VERSION 5.8 ;
BUSBITCHARS "[]" ;
DIVIDERCHAR "/" ;
UNITS
    DATABASE MICRONS 1000 ;
END UNITS

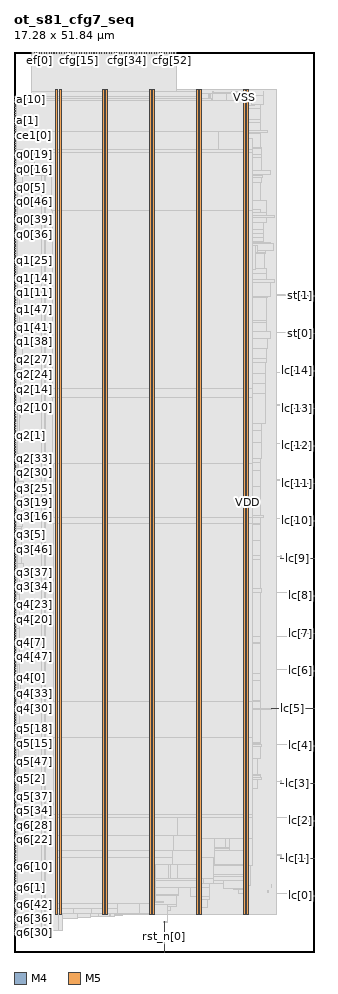
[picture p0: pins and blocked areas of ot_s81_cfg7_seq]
MACRO ot_s81_cfg7_seq
  FOREIGN ot_s81_cfg7_seq 0 0 ;
  CLASS BLOCK ;
  SIZE 17.28 BY 51.84 ;
  PIN a[0]
    DIRECTION OUTPUT ;
    USE SIGNAL ;
    PORT
      LAYER M4 ;
        RECT  0 47.76 0.084 47.784 ;
    END
  END a[0]
  PIN a[10]
    DIRECTION OUTPUT ;
    USE SIGNAL ;
    PORT
      LAYER M4 ;
        RECT  0 49.104 0.084 49.128 ;
    END
  END a[10]
  PIN a[11]
    DIRECTION OUTPUT ;
    USE SIGNAL ;
    PORT
      LAYER M4 ;
        RECT  0 49.248 0.084 49.272 ;
    END
  END a[11]
  PIN a[1]
    DIRECTION OUTPUT ;
    USE SIGNAL ;
    PORT
      LAYER M4 ;
        RECT  0 47.904 0.084 47.928 ;
    END
  END a[1]
  PIN a[2]
    DIRECTION OUTPUT ;
    USE SIGNAL ;
    PORT
      LAYER M4 ;
        RECT  0 48.048 0.084 48.072 ;
    END
  END a[2]
  PIN a[3]
    DIRECTION OUTPUT ;
    USE SIGNAL ;
    PORT
      LAYER M4 ;
        RECT  0 48.144 0.084 48.168 ;
    END
  END a[3]
  PIN a[4]
    DIRECTION OUTPUT ;
    USE SIGNAL ;
    PORT
      LAYER M4 ;
        RECT  0 48.288 0.084 48.312 ;
    END
  END a[4]
  PIN a[5]
    DIRECTION OUTPUT ;
    USE SIGNAL ;
    PORT
      LAYER M4 ;
        RECT  0 48.432 0.084 48.456 ;
    END
  END a[5]
  PIN a[6]
    DIRECTION OUTPUT ;
    USE SIGNAL ;
    PORT
      LAYER M4 ;
        RECT  0 48.576 0.084 48.6 ;
    END
  END a[6]
  PIN a[7]
    DIRECTION OUTPUT ;
    USE SIGNAL ;
    PORT
      LAYER M4 ;
        RECT  0 48.72 0.084 48.744 ;
    END
  END a[7]
  PIN a[8]
    DIRECTION OUTPUT ;
    USE SIGNAL ;
    PORT
      LAYER M4 ;
        RECT  0 48.816 0.084 48.84 ;
    END
  END a[8]
  PIN a[9]
    DIRECTION OUTPUT ;
    USE SIGNAL ;
    PORT
      LAYER M4 ;
        RECT  0 48.96 0.084 48.984 ;
    END
  END a[9]
  PIN ce0[0]
    DIRECTION OUTPUT ;
    USE SIGNAL ;
    PORT
      LAYER M4 ;
        RECT  0 47.616 0.084 47.64 ;
    END
  END ce0[0]
  PIN ce1[0]
    DIRECTION OUTPUT ;
    USE SIGNAL ;
    PORT
      LAYER M4 ;
        RECT  0 47.472 0.084 47.496 ;
    END
  END ce1[0]
  PIN ce2[0]
    DIRECTION OUTPUT ;
    USE SIGNAL ;
    PORT
      LAYER M4 ;
        RECT  0 47.376 0.084 47.4 ;
    END
  END ce2[0]
  PIN ce3[0]
    DIRECTION OUTPUT ;
    USE SIGNAL ;
    PORT
      LAYER M4 ;
        RECT  0 47.232 0.084 47.256 ;
    END
  END ce3[0]
  PIN ce4[0]
    DIRECTION OUTPUT ;
    USE SIGNAL ;
    PORT
      LAYER M4 ;
        RECT  0 47.088 0.084 47.112 ;
    END
  END ce4[0]
  PIN ce5[0]
    DIRECTION OUTPUT ;
    USE SIGNAL ;
    PORT
      LAYER M4 ;
        RECT  0 46.944 0.084 46.968 ;
    END
  END ce5[0]
  PIN ce6[0]
    DIRECTION OUTPUT ;
    USE SIGNAL ;
    PORT
      LAYER M4 ;
        RECT  0 46.8 0.084 46.824 ;
    END
  END ce6[0]
  PIN cfg[0]
    DIRECTION OUTPUT ;
    USE SIGNAL ;
    PORT
      LAYER M5 ;
        RECT  1.584 51.756 1.608 51.84 ;
    END
  END cfg[0]
  PIN cfg[10]
    DIRECTION OUTPUT ;
    USE SIGNAL ;
    PORT
      LAYER M5 ;
        RECT  3.024 51.756 3.048 51.84 ;
    END
  END cfg[10]
  PIN cfg[11]
    DIRECTION OUTPUT ;
    USE SIGNAL ;
    PORT
      LAYER M5 ;
        RECT  3.168 51.756 3.192 51.84 ;
    END
  END cfg[11]
  PIN cfg[12]
    DIRECTION OUTPUT ;
    USE SIGNAL ;
    PORT
      LAYER M5 ;
        RECT  3.312 51.756 3.336 51.84 ;
    END
  END cfg[12]
  PIN cfg[13]
    DIRECTION OUTPUT ;
    USE SIGNAL ;
    PORT
      LAYER M5 ;
        RECT  3.456 51.756 3.48 51.84 ;
    END
  END cfg[13]
  PIN cfg[14]
    DIRECTION OUTPUT ;
    USE SIGNAL ;
    PORT
      LAYER M5 ;
        RECT  3.6 51.756 3.624 51.84 ;
    END
  END cfg[14]
  PIN cfg[15]
    DIRECTION OUTPUT ;
    USE SIGNAL ;
    PORT
      LAYER M5 ;
        RECT  3.744 51.756 3.768 51.84 ;
    END
  END cfg[15]
  PIN cfg[16]
    DIRECTION OUTPUT ;
    USE SIGNAL ;
    PORT
      LAYER M5 ;
        RECT  3.888 51.756 3.912 51.84 ;
    END
  END cfg[16]
  PIN cfg[17]
    DIRECTION OUTPUT ;
    USE SIGNAL ;
    PORT
      LAYER M5 ;
        RECT  4.032 51.756 4.056 51.84 ;
    END
  END cfg[17]
  PIN cfg[18]
    DIRECTION OUTPUT ;
    USE SIGNAL ;
    PORT
      LAYER M5 ;
        RECT  4.176 51.756 4.2 51.84 ;
    END
  END cfg[18]
  PIN cfg[19]
    DIRECTION OUTPUT ;
    USE SIGNAL ;
    PORT
      LAYER M5 ;
        RECT  4.32 51.756 4.344 51.84 ;
    END
  END cfg[19]
  PIN cfg[1]
    DIRECTION OUTPUT ;
    USE SIGNAL ;
    PORT
      LAYER M5 ;
        RECT  1.728 51.756 1.752 51.84 ;
    END
  END cfg[1]
  PIN cfg[20]
    DIRECTION OUTPUT ;
    USE SIGNAL ;
    PORT
      LAYER M5 ;
        RECT  4.464 51.756 4.488 51.84 ;
    END
  END cfg[20]
  PIN cfg[21]
    DIRECTION OUTPUT ;
    USE SIGNAL ;
    PORT
      LAYER M5 ;
        RECT  4.608 51.756 4.632 51.84 ;
    END
  END cfg[21]
  PIN cfg[22]
    DIRECTION OUTPUT ;
    USE SIGNAL ;
    PORT
      LAYER M5 ;
        RECT  4.752 51.756 4.776 51.84 ;
    END
  END cfg[22]
  PIN cfg[23]
    DIRECTION OUTPUT ;
    USE SIGNAL ;
    PORT
      LAYER M5 ;
        RECT  4.896 51.756 4.92 51.84 ;
    END
  END cfg[23]
  PIN cfg[24]
    DIRECTION OUTPUT ;
    USE SIGNAL ;
    PORT
      LAYER M5 ;
        RECT  5.04 51.756 5.064 51.84 ;
    END
  END cfg[24]
  PIN cfg[25]
    DIRECTION OUTPUT ;
    USE SIGNAL ;
    PORT
      LAYER M5 ;
        RECT  5.184 51.756 5.208 51.84 ;
    END
  END cfg[25]
  PIN cfg[26]
    DIRECTION OUTPUT ;
    USE SIGNAL ;
    PORT
      LAYER M5 ;
        RECT  5.328 51.756 5.352 51.84 ;
    END
  END cfg[26]
  PIN cfg[27]
    DIRECTION OUTPUT ;
    USE SIGNAL ;
    PORT
      LAYER M5 ;
        RECT  5.472 51.756 5.496 51.84 ;
    END
  END cfg[27]
  PIN cfg[28]
    DIRECTION OUTPUT ;
    USE SIGNAL ;
    PORT
      LAYER M5 ;
        RECT  5.616 51.756 5.64 51.84 ;
    END
  END cfg[28]
  PIN cfg[29]
    DIRECTION OUTPUT ;
    USE SIGNAL ;
    PORT
      LAYER M5 ;
        RECT  5.76 51.756 5.784 51.84 ;
    END
  END cfg[29]
  PIN cfg[2]
    DIRECTION OUTPUT ;
    USE SIGNAL ;
    PORT
      LAYER M5 ;
        RECT  1.872 51.756 1.896 51.84 ;
    END
  END cfg[2]
  PIN cfg[30]
    DIRECTION OUTPUT ;
    USE SIGNAL ;
    PORT
      LAYER M5 ;
        RECT  5.904 51.756 5.928 51.84 ;
    END
  END cfg[30]
  PIN cfg[31]
    DIRECTION OUTPUT ;
    USE SIGNAL ;
    PORT
      LAYER M5 ;
        RECT  6.048 51.756 6.072 51.84 ;
    END
  END cfg[31]
  PIN cfg[32]
    DIRECTION OUTPUT ;
    USE SIGNAL ;
    PORT
      LAYER M5 ;
        RECT  6.192 51.756 6.216 51.84 ;
    END
  END cfg[32]
  PIN cfg[33]
    DIRECTION OUTPUT ;
    USE SIGNAL ;
    PORT
      LAYER M5 ;
        RECT  6.336 51.756 6.36 51.84 ;
    END
  END cfg[33]
  PIN cfg[34]
    DIRECTION OUTPUT ;
    USE SIGNAL ;
    PORT
      LAYER M5 ;
        RECT  6.48 51.756 6.504 51.84 ;
    END
  END cfg[34]
  PIN cfg[35]
    DIRECTION OUTPUT ;
    USE SIGNAL ;
    PORT
      LAYER M5 ;
        RECT  6.624 51.756 6.648 51.84 ;
    END
  END cfg[35]
  PIN cfg[36]
    DIRECTION OUTPUT ;
    USE SIGNAL ;
    PORT
      LAYER M5 ;
        RECT  6.768 51.756 6.792 51.84 ;
    END
  END cfg[36]
  PIN cfg[37]
    DIRECTION OUTPUT ;
    USE SIGNAL ;
    PORT
      LAYER M5 ;
        RECT  6.912 51.756 6.936 51.84 ;
    END
  END cfg[37]
  PIN cfg[38]
    DIRECTION OUTPUT ;
    USE SIGNAL ;
    PORT
      LAYER M5 ;
        RECT  7.056 51.756 7.08 51.84 ;
    END
  END cfg[38]
  PIN cfg[39]
    DIRECTION OUTPUT ;
    USE SIGNAL ;
    PORT
      LAYER M5 ;
        RECT  7.2 51.756 7.224 51.84 ;
    END
  END cfg[39]
  PIN cfg[3]
    DIRECTION OUTPUT ;
    USE SIGNAL ;
    PORT
      LAYER M5 ;
        RECT  2.016 51.756 2.04 51.84 ;
    END
  END cfg[3]
  PIN cfg[40]
    DIRECTION OUTPUT ;
    USE SIGNAL ;
    PORT
      LAYER M5 ;
        RECT  7.344 51.756 7.368 51.84 ;
    END
  END cfg[40]
  PIN cfg[41]
    DIRECTION OUTPUT ;
    USE SIGNAL ;
    PORT
      LAYER M5 ;
        RECT  7.488 51.756 7.512 51.84 ;
    END
  END cfg[41]
  PIN cfg[42]
    DIRECTION OUTPUT ;
    USE SIGNAL ;
    PORT
      LAYER M5 ;
        RECT  7.632 51.756 7.656 51.84 ;
    END
  END cfg[42]
  PIN cfg[43]
    DIRECTION OUTPUT ;
    USE SIGNAL ;
    PORT
      LAYER M5 ;
        RECT  7.776 51.756 7.8 51.84 ;
    END
  END cfg[43]
  PIN cfg[44]
    DIRECTION OUTPUT ;
    USE SIGNAL ;
    PORT
      LAYER M5 ;
        RECT  7.92 51.756 7.944 51.84 ;
    END
  END cfg[44]
  PIN cfg[45]
    DIRECTION OUTPUT ;
    USE SIGNAL ;
    PORT
      LAYER M5 ;
        RECT  8.064 51.756 8.088 51.84 ;
    END
  END cfg[45]
  PIN cfg[46]
    DIRECTION OUTPUT ;
    USE SIGNAL ;
    PORT
      LAYER M5 ;
        RECT  8.208 51.756 8.232 51.84 ;
    END
  END cfg[46]
  PIN cfg[47]
    DIRECTION OUTPUT ;
    USE SIGNAL ;
    PORT
      LAYER M5 ;
        RECT  8.352 51.756 8.376 51.84 ;
    END
  END cfg[47]
  PIN cfg[48]
    DIRECTION OUTPUT ;
    USE SIGNAL ;
    PORT
      LAYER M5 ;
        RECT  8.496 51.756 8.52 51.84 ;
    END
  END cfg[48]
  PIN cfg[49]
    DIRECTION OUTPUT ;
    USE SIGNAL ;
    PORT
      LAYER M5 ;
        RECT  8.64 51.756 8.664 51.84 ;
    END
  END cfg[49]
  PIN cfg[4]
    DIRECTION OUTPUT ;
    USE SIGNAL ;
    PORT
      LAYER M5 ;
        RECT  2.16 51.756 2.184 51.84 ;
    END
  END cfg[4]
  PIN cfg[50]
    DIRECTION OUTPUT ;
    USE SIGNAL ;
    PORT
      LAYER M5 ;
        RECT  8.784 51.756 8.808 51.84 ;
    END
  END cfg[50]
  PIN cfg[51]
    DIRECTION OUTPUT ;
    USE SIGNAL ;
    PORT
      LAYER M5 ;
        RECT  8.928 51.756 8.952 51.84 ;
    END
  END cfg[51]
  PIN cfg[52]
    DIRECTION OUTPUT ;
    USE SIGNAL ;
    PORT
      LAYER M5 ;
        RECT  9.072 51.756 9.096 51.84 ;
    END
  END cfg[52]
  PIN cfg[53]
    DIRECTION OUTPUT ;
    USE SIGNAL ;
    PORT
      LAYER M5 ;
        RECT  9.216 51.756 9.24 51.84 ;
    END
  END cfg[53]
  PIN cfg[5]
    DIRECTION OUTPUT ;
    USE SIGNAL ;
    PORT
      LAYER M5 ;
        RECT  2.304 51.756 2.328 51.84 ;
    END
  END cfg[5]
  PIN cfg[6]
    DIRECTION OUTPUT ;
    USE SIGNAL ;
    PORT
      LAYER M5 ;
        RECT  2.448 51.756 2.472 51.84 ;
    END
  END cfg[6]
  PIN cfg[7]
    DIRECTION OUTPUT ;
    USE SIGNAL ;
    PORT
      LAYER M5 ;
        RECT  2.592 51.756 2.616 51.84 ;
    END
  END cfg[7]
  PIN cfg[8]
    DIRECTION OUTPUT ;
    USE SIGNAL ;
    PORT
      LAYER M5 ;
        RECT  2.736 51.756 2.76 51.84 ;
    END
  END cfg[8]
  PIN cfg[9]
    DIRECTION OUTPUT ;
    USE SIGNAL ;
    PORT
      LAYER M5 ;
        RECT  2.88 51.756 2.904 51.84 ;
    END
  END cfg[9]
  PIN clk[0]
    DIRECTION INPUT ;
    USE SIGNAL ;
    PORT
      LAYER M4 ;
        RECT  0 27.072 0.084 27.096 ;
    END
  END clk[0]
  PIN ef[0]
    DIRECTION INPUT ;
    USE SIGNAL ;
    PORT
      LAYER M5 ;
        RECT  1.44 51.756 1.464 51.84 ;
    END
  END ef[0]
  PIN ef[1]
    DIRECTION INPUT ;
    USE SIGNAL ;
    PORT
      LAYER M5 ;
        RECT  1.008 51.756 1.032 51.84 ;
    END
  END ef[1]
  PIN go_e[0]
    DIRECTION OUTPUT ;
    USE SIGNAL ;
    PORT
      LAYER M5 ;
        RECT  9.36 51.756 9.384 51.84 ;
    END
  END go_e[0]
  PIN go_tag[0]
    DIRECTION OUTPUT ;
    USE SIGNAL ;
    PORT
      LAYER M5 ;
        RECT  1.152 51.756 1.176 51.84 ;
    END
  END go_tag[0]
  PIN go_tag[1]
    DIRECTION OUTPUT ;
    USE SIGNAL ;
    PORT
      LAYER M5 ;
        RECT  1.296 51.756 1.32 51.84 ;
    END
  END go_tag[1]
  PIN lc[0]
    DIRECTION INPUT ;
    USE SIGNAL ;
    PORT
      LAYER M4 ;
        RECT  17.196 3.216 17.28 3.24 ;
    END
    PORT
      LAYER M4 ;
        RECT  15.937 3.216 17.244 3.24 ;
    END
  END lc[0]
  PIN lc[10]
    DIRECTION INPUT ;
    USE SIGNAL ;
    PORT
      LAYER M4 ;
        RECT  17.196 24.816 17.28 24.84 ;
    END
    PORT
      LAYER M4 ;
        RECT  15.361 24.816 17.244 24.84 ;
    END
  END lc[10]
  PIN lc[11]
    DIRECTION INPUT ;
    USE SIGNAL ;
    PORT
      LAYER M4 ;
        RECT  17.196 26.976 17.28 27 ;
    END
    PORT
      LAYER M4 ;
        RECT  15.361 26.976 17.244 27 ;
    END
  END lc[11]
  PIN lc[12]
    DIRECTION INPUT ;
    USE SIGNAL ;
    PORT
      LAYER M4 ;
        RECT  17.196 29.136 17.28 29.16 ;
    END
    PORT
      LAYER M4 ;
        RECT  15.937 29.136 17.244 29.16 ;
    END
  END lc[12]
  PIN lc[13]
    DIRECTION INPUT ;
    USE SIGNAL ;
    PORT
      LAYER M4 ;
        RECT  17.196 31.296 17.28 31.32 ;
    END
    PORT
      LAYER M4 ;
        RECT  15.937 31.296 17.244 31.32 ;
    END
  END lc[13]
  PIN lc[14]
    DIRECTION INPUT ;
    USE SIGNAL ;
    PORT
      LAYER M4 ;
        RECT  17.196 33.456 17.28 33.48 ;
    END
    PORT
      LAYER M4 ;
        RECT  15.397 33.456 17.244 33.48 ;
    END
  END lc[14]
  PIN lc[1]
    DIRECTION INPUT ;
    USE SIGNAL ;
    PORT
      LAYER M4 ;
        RECT  17.196 5.376 17.28 5.4 ;
    END
    PORT
      LAYER M4 ;
        RECT  15.361 5.376 17.244 5.4 ;
    END
  END lc[1]
  PIN lc[2]
    DIRECTION INPUT ;
    USE SIGNAL ;
    PORT
      LAYER M4 ;
        RECT  17.196 7.536 17.28 7.56 ;
    END
    PORT
      LAYER M4 ;
        RECT  15.937 7.536 17.244 7.56 ;
    END
  END lc[2]
  PIN lc[3]
    DIRECTION INPUT ;
    USE SIGNAL ;
    PORT
      LAYER M4 ;
        RECT  17.196 9.696 17.28 9.72 ;
    END
    PORT
      LAYER M4 ;
        RECT  15.361 9.696 17.244 9.72 ;
    END
  END lc[3]
  PIN lc[4]
    DIRECTION INPUT ;
    USE SIGNAL ;
    PORT
      LAYER M4 ;
        RECT  17.196 11.856 17.28 11.88 ;
    END
    PORT
      LAYER M4 ;
        RECT  15.937 11.856 17.244 11.88 ;
    END
  END lc[4]
  PIN lc[5]
    DIRECTION INPUT ;
    USE SIGNAL ;
    PORT
      LAYER M4 ;
        RECT  17.196 14.016 17.28 14.04 ;
    END
    PORT
      LAYER M4 ;
        RECT  14.821 14.016 17.244 14.04 ;
    END
  END lc[5]
  PIN lc[6]
    DIRECTION INPUT ;
    USE SIGNAL ;
    PORT
      LAYER M4 ;
        RECT  17.196 16.176 17.28 16.2 ;
    END
    PORT
      LAYER M4 ;
        RECT  17.161 16.176 17.244 16.2 ;
    END
  END lc[6]
  PIN lc[7]
    DIRECTION INPUT ;
    USE SIGNAL ;
    PORT
      LAYER M4 ;
        RECT  17.196 18.336 17.28 18.36 ;
    END
    PORT
      LAYER M4 ;
        RECT  15.973 18.336 17.244 18.36 ;
    END
  END lc[7]
  PIN lc[8]
    DIRECTION INPUT ;
    USE SIGNAL ;
    PORT
      LAYER M4 ;
        RECT  17.196 20.496 17.28 20.52 ;
    END
    PORT
      LAYER M4 ;
        RECT  15.937 20.496 17.244 20.52 ;
    END
  END lc[8]
  PIN lc[9]
    DIRECTION INPUT ;
    USE SIGNAL ;
    PORT
      LAYER M4 ;
        RECT  17.196 22.656 17.28 22.68 ;
    END
    PORT
      LAYER M4 ;
        RECT  15.361 22.656 17.244 22.68 ;
    END
  END lc[9]
  PIN q0[0]
    DIRECTION INPUT ;
    USE SIGNAL ;
    PORT
      LAYER M4 ;
        RECT  0 42.24 0.084 42.264 ;
    END
  END q0[0]
  PIN q0[10]
    DIRECTION INPUT ;
    USE SIGNAL ;
    PORT
      LAYER M4 ;
        RECT  0 44.256 0.084 44.28 ;
    END
  END q0[10]
  PIN q0[11]
    DIRECTION INPUT ;
    USE SIGNAL ;
    PORT
      LAYER M4 ;
        RECT  0 44.4 0.084 44.424 ;
    END
  END q0[11]
  PIN q0[12]
    DIRECTION INPUT ;
    USE SIGNAL ;
    PORT
      LAYER M4 ;
        RECT  0 44.544 0.084 44.568 ;
    END
  END q0[12]
  PIN q0[13]
    DIRECTION INPUT ;
    USE SIGNAL ;
    PORT
      LAYER M4 ;
        RECT  0 44.688 0.084 44.712 ;
    END
  END q0[13]
  PIN q0[14]
    DIRECTION INPUT ;
    USE SIGNAL ;
    PORT
      LAYER M4 ;
        RECT  0 44.784 0.084 44.808 ;
    END
  END q0[14]
  PIN q0[15]
    DIRECTION INPUT ;
    USE SIGNAL ;
    PORT
      LAYER M4 ;
        RECT  0 44.928 0.084 44.952 ;
    END
  END q0[15]
  PIN q0[16]
    DIRECTION INPUT ;
    USE SIGNAL ;
    PORT
      LAYER M4 ;
        RECT  0 45.072 0.084 45.096 ;
    END
  END q0[16]
  PIN q0[17]
    DIRECTION INPUT ;
    USE SIGNAL ;
    PORT
      LAYER M4 ;
        RECT  0 45.216 0.084 45.24 ;
    END
  END q0[17]
  PIN q0[18]
    DIRECTION INPUT ;
    USE SIGNAL ;
    PORT
      LAYER M4 ;
        RECT  0 45.36 0.084 45.384 ;
    END
  END q0[18]
  PIN q0[19]
    DIRECTION INPUT ;
    USE SIGNAL ;
    PORT
      LAYER M4 ;
        RECT  0 45.456 0.084 45.48 ;
    END
  END q0[19]
  PIN q0[1]
    DIRECTION INPUT ;
    USE SIGNAL ;
    PORT
      LAYER M4 ;
        RECT  0 42.672 0.084 42.696 ;
    END
  END q0[1]
  PIN q0[20]
    DIRECTION INPUT ;
    USE SIGNAL ;
    PORT
      LAYER M4 ;
        RECT  0 45.6 0.084 45.624 ;
    END
  END q0[20]
  PIN q0[21]
    DIRECTION INPUT ;
    USE SIGNAL ;
    PORT
      LAYER M4 ;
        RECT  0 45.744 0.084 45.768 ;
    END
  END q0[21]
  PIN q0[22]
    DIRECTION INPUT ;
    USE SIGNAL ;
    PORT
      LAYER M4 ;
        RECT  0 45.888 0.084 45.912 ;
    END
  END q0[22]
  PIN q0[23]
    DIRECTION INPUT ;
    USE SIGNAL ;
    PORT
      LAYER M4 ;
        RECT  0 46.032 0.084 46.056 ;
    END
  END q0[23]
  PIN q0[24]
    DIRECTION INPUT ;
    USE SIGNAL ;
    PORT
      LAYER M4 ;
        RECT  0 46.128 0.084 46.152 ;
    END
  END q0[24]
  PIN q0[25]
    DIRECTION INPUT ;
    USE SIGNAL ;
    PORT
      LAYER M4 ;
        RECT  0 46.272 0.084 46.296 ;
    END
  END q0[25]
  PIN q0[26]
    DIRECTION INPUT ;
    USE SIGNAL ;
    PORT
      LAYER M4 ;
        RECT  0 46.416 0.084 46.44 ;
    END
  END q0[26]
  PIN q0[27]
    DIRECTION INPUT ;
    USE SIGNAL ;
    PORT
      LAYER M4 ;
        RECT  0 46.56 0.084 46.584 ;
    END
  END q0[27]
  PIN q0[28]
    DIRECTION INPUT ;
    USE SIGNAL ;
    PORT
      LAYER M4 ;
        RECT  0 46.704 0.084 46.728 ;
    END
  END q0[28]
  PIN q0[29]
    DIRECTION INPUT ;
    USE SIGNAL ;
    PORT
      LAYER M4 ;
        RECT  0 40.368 0.084 40.392 ;
    END
  END q0[29]
  PIN q0[2]
    DIRECTION INPUT ;
    USE SIGNAL ;
    PORT
      LAYER M4 ;
        RECT  0 42.912 0.084 42.936 ;
    END
  END q0[2]
  PIN q0[30]
    DIRECTION INPUT ;
    USE SIGNAL ;
    PORT
      LAYER M4 ;
        RECT  0 40.512 0.084 40.536 ;
    END
  END q0[30]
  PIN q0[31]
    DIRECTION INPUT ;
    USE SIGNAL ;
    PORT
      LAYER M4 ;
        RECT  0 40.656 0.084 40.68 ;
    END
  END q0[31]
  PIN q0[32]
    DIRECTION INPUT ;
    USE SIGNAL ;
    PORT
      LAYER M4 ;
        RECT  0 40.752 0.084 40.776 ;
    END
  END q0[32]
  PIN q0[33]
    DIRECTION INPUT ;
    USE SIGNAL ;
    PORT
      LAYER M4 ;
        RECT  0 40.896 0.084 40.92 ;
    END
  END q0[33]
  PIN q0[34]
    DIRECTION INPUT ;
    USE SIGNAL ;
    PORT
      LAYER M4 ;
        RECT  0 41.04 0.084 41.064 ;
    END
  END q0[34]
  PIN q0[35]
    DIRECTION INPUT ;
    USE SIGNAL ;
    PORT
      LAYER M4 ;
        RECT  0 41.184 0.084 41.208 ;
    END
  END q0[35]
  PIN q0[36]
    DIRECTION INPUT ;
    USE SIGNAL ;
    PORT
      LAYER M4 ;
        RECT  0 41.328 0.084 41.352 ;
    END
  END q0[36]
  PIN q0[37]
    DIRECTION INPUT ;
    USE SIGNAL ;
    PORT
      LAYER M4 ;
        RECT  0 41.424 0.084 41.448 ;
    END
  END q0[37]
  PIN q0[38]
    DIRECTION INPUT ;
    USE SIGNAL ;
    PORT
      LAYER M4 ;
        RECT  0 41.568 0.084 41.592 ;
    END
  END q0[38]
  PIN q0[39]
    DIRECTION INPUT ;
    USE SIGNAL ;
    PORT
      LAYER M4 ;
        RECT  0 41.712 0.084 41.736 ;
    END
  END q0[39]
  PIN q0[3]
    DIRECTION INPUT ;
    USE SIGNAL ;
    PORT
      LAYER M4 ;
        RECT  0 43.056 0.084 43.08 ;
    END
  END q0[3]
  PIN q0[40]
    DIRECTION INPUT ;
    USE SIGNAL ;
    PORT
      LAYER M4 ;
        RECT  0 41.856 0.084 41.88 ;
    END
  END q0[40]
  PIN q0[41]
    DIRECTION INPUT ;
    USE SIGNAL ;
    PORT
      LAYER M4 ;
        RECT  0 42 0.084 42.024 ;
    END
  END q0[41]
  PIN q0[42]
    DIRECTION INPUT ;
    USE SIGNAL ;
    PORT
      LAYER M4 ;
        RECT  0 42.096 0.084 42.12 ;
    END
  END q0[42]
  PIN q0[43]
    DIRECTION INPUT ;
    USE SIGNAL ;
    PORT
      LAYER M4 ;
        RECT  0 42.384 0.084 42.408 ;
    END
  END q0[43]
  PIN q0[44]
    DIRECTION INPUT ;
    USE SIGNAL ;
    PORT
      LAYER M4 ;
        RECT  0 42.528 0.084 42.552 ;
    END
  END q0[44]
  PIN q0[45]
    DIRECTION INPUT ;
    USE SIGNAL ;
    PORT
      LAYER M4 ;
        RECT  0 42.768 0.084 42.792 ;
    END
  END q0[45]
  PIN q0[46]
    DIRECTION INPUT ;
    USE SIGNAL ;
    PORT
      LAYER M4 ;
        RECT  0 43.2 0.084 43.224 ;
    END
  END q0[46]
  PIN q0[47]
    DIRECTION INPUT ;
    USE SIGNAL ;
    PORT
      LAYER M4 ;
        RECT  0 43.44 0.084 43.464 ;
    END
  END q0[47]
  PIN q0[4]
    DIRECTION INPUT ;
    USE SIGNAL ;
    PORT
      LAYER M4 ;
        RECT  0 43.344 0.084 43.368 ;
    END
  END q0[4]
  PIN q0[5]
    DIRECTION INPUT ;
    USE SIGNAL ;
    PORT
      LAYER M4 ;
        RECT  0 43.584 0.084 43.608 ;
    END
  END q0[5]
  PIN q0[6]
    DIRECTION INPUT ;
    USE SIGNAL ;
    PORT
      LAYER M4 ;
        RECT  0 43.728 0.084 43.752 ;
    END
  END q0[6]
  PIN q0[7]
    DIRECTION INPUT ;
    USE SIGNAL ;
    PORT
      LAYER M4 ;
        RECT  0 43.872 0.084 43.896 ;
    END
  END q0[7]
  PIN q0[8]
    DIRECTION INPUT ;
    USE SIGNAL ;
    PORT
      LAYER M4 ;
        RECT  0 44.016 0.084 44.04 ;
    END
  END q0[8]
  PIN q0[9]
    DIRECTION INPUT ;
    USE SIGNAL ;
    PORT
      LAYER M4 ;
        RECT  0 44.112 0.084 44.136 ;
    END
  END q0[9]
  PIN q1[0]
    DIRECTION INPUT ;
    USE SIGNAL ;
    PORT
      LAYER M4 ;
        RECT  0 35.808 0.084 35.832 ;
    END
  END q1[0]
  PIN q1[10]
    DIRECTION INPUT ;
    USE SIGNAL ;
    PORT
      LAYER M4 ;
        RECT  0 37.824 0.084 37.848 ;
    END
  END q1[10]
  PIN q1[11]
    DIRECTION INPUT ;
    USE SIGNAL ;
    PORT
      LAYER M4 ;
        RECT  0 37.968 0.084 37.992 ;
    END
  END q1[11]
  PIN q1[12]
    DIRECTION INPUT ;
    USE SIGNAL ;
    PORT
      LAYER M4 ;
        RECT  0 38.064 0.084 38.088 ;
    END
  END q1[12]
  PIN q1[13]
    DIRECTION INPUT ;
    USE SIGNAL ;
    PORT
      LAYER M4 ;
        RECT  0 38.208 0.084 38.232 ;
    END
  END q1[13]
  PIN q1[14]
    DIRECTION INPUT ;
    USE SIGNAL ;
    PORT
      LAYER M4 ;
        RECT  0 38.352 0.084 38.376 ;
    END
  END q1[14]
  PIN q1[15]
    DIRECTION INPUT ;
    USE SIGNAL ;
    PORT
      LAYER M4 ;
        RECT  0 38.496 0.084 38.52 ;
    END
  END q1[15]
  PIN q1[16]
    DIRECTION INPUT ;
    USE SIGNAL ;
    PORT
      LAYER M4 ;
        RECT  0 38.64 0.084 38.664 ;
    END
  END q1[16]
  PIN q1[17]
    DIRECTION INPUT ;
    USE SIGNAL ;
    PORT
      LAYER M4 ;
        RECT  0 38.736 0.084 38.76 ;
    END
  END q1[17]
  PIN q1[18]
    DIRECTION INPUT ;
    USE SIGNAL ;
    PORT
      LAYER M4 ;
        RECT  0 38.88 0.084 38.904 ;
    END
  END q1[18]
  PIN q1[19]
    DIRECTION INPUT ;
    USE SIGNAL ;
    PORT
      LAYER M4 ;
        RECT  0 39.024 0.084 39.048 ;
    END
  END q1[19]
  PIN q1[1]
    DIRECTION INPUT ;
    USE SIGNAL ;
    PORT
      LAYER M4 ;
        RECT  0 36.192 0.084 36.216 ;
    END
  END q1[1]
  PIN q1[20]
    DIRECTION INPUT ;
    USE SIGNAL ;
    PORT
      LAYER M4 ;
        RECT  0 39.168 0.084 39.192 ;
    END
  END q1[20]
  PIN q1[21]
    DIRECTION INPUT ;
    USE SIGNAL ;
    PORT
      LAYER M4 ;
        RECT  0 39.312 0.084 39.336 ;
    END
  END q1[21]
  PIN q1[22]
    DIRECTION INPUT ;
    USE SIGNAL ;
    PORT
      LAYER M4 ;
        RECT  0 39.408 0.084 39.432 ;
    END
  END q1[22]
  PIN q1[23]
    DIRECTION INPUT ;
    USE SIGNAL ;
    PORT
      LAYER M4 ;
        RECT  0 39.552 0.084 39.576 ;
    END
  END q1[23]
  PIN q1[24]
    DIRECTION INPUT ;
    USE SIGNAL ;
    PORT
      LAYER M4 ;
        RECT  0 39.696 0.084 39.72 ;
    END
  END q1[24]
  PIN q1[25]
    DIRECTION INPUT ;
    USE SIGNAL ;
    PORT
      LAYER M4 ;
        RECT  0 39.84 0.084 39.864 ;
    END
  END q1[25]
  PIN q1[26]
    DIRECTION INPUT ;
    USE SIGNAL ;
    PORT
      LAYER M4 ;
        RECT  0 39.984 0.084 40.008 ;
    END
  END q1[26]
  PIN q1[27]
    DIRECTION INPUT ;
    USE SIGNAL ;
    PORT
      LAYER M4 ;
        RECT  0 40.08 0.084 40.104 ;
    END
  END q1[27]
  PIN q1[28]
    DIRECTION INPUT ;
    USE SIGNAL ;
    PORT
      LAYER M4 ;
        RECT  0 40.224 0.084 40.248 ;
    END
  END q1[28]
  PIN q1[29]
    DIRECTION INPUT ;
    USE SIGNAL ;
    PORT
      LAYER M4 ;
        RECT  0 33.936 0.084 33.96 ;
    END
  END q1[29]
  PIN q1[2]
    DIRECTION INPUT ;
    USE SIGNAL ;
    PORT
      LAYER M4 ;
        RECT  0 36.48 0.084 36.504 ;
    END
  END q1[2]
  PIN q1[30]
    DIRECTION INPUT ;
    USE SIGNAL ;
    PORT
      LAYER M4 ;
        RECT  0 34.032 0.084 34.056 ;
    END
  END q1[30]
  PIN q1[31]
    DIRECTION INPUT ;
    USE SIGNAL ;
    PORT
      LAYER M4 ;
        RECT  0 34.176 0.084 34.2 ;
    END
  END q1[31]
  PIN q1[32]
    DIRECTION INPUT ;
    USE SIGNAL ;
    PORT
      LAYER M4 ;
        RECT  0 34.32 0.084 34.344 ;
    END
  END q1[32]
  PIN q1[33]
    DIRECTION INPUT ;
    USE SIGNAL ;
    PORT
      LAYER M4 ;
        RECT  0 34.464 0.084 34.488 ;
    END
  END q1[33]
  PIN q1[34]
    DIRECTION INPUT ;
    USE SIGNAL ;
    PORT
      LAYER M4 ;
        RECT  0 34.608 0.084 34.632 ;
    END
  END q1[34]
  PIN q1[35]
    DIRECTION INPUT ;
    USE SIGNAL ;
    PORT
      LAYER M4 ;
        RECT  0 34.704 0.084 34.728 ;
    END
  END q1[35]
  PIN q1[36]
    DIRECTION INPUT ;
    USE SIGNAL ;
    PORT
      LAYER M4 ;
        RECT  0 34.848 0.084 34.872 ;
    END
  END q1[36]
  PIN q1[37]
    DIRECTION INPUT ;
    USE SIGNAL ;
    PORT
      LAYER M4 ;
        RECT  0 34.992 0.084 35.016 ;
    END
  END q1[37]
  PIN q1[38]
    DIRECTION INPUT ;
    USE SIGNAL ;
    PORT
      LAYER M4 ;
        RECT  0 35.136 0.084 35.16 ;
    END
  END q1[38]
  PIN q1[39]
    DIRECTION INPUT ;
    USE SIGNAL ;
    PORT
      LAYER M4 ;
        RECT  0 35.28 0.084 35.304 ;
    END
  END q1[39]
  PIN q1[3]
    DIRECTION INPUT ;
    USE SIGNAL ;
    PORT
      LAYER M4 ;
        RECT  0 36.624 0.084 36.648 ;
    END
  END q1[3]
  PIN q1[40]
    DIRECTION INPUT ;
    USE SIGNAL ;
    PORT
      LAYER M4 ;
        RECT  0 35.376 0.084 35.4 ;
    END
  END q1[40]
  PIN q1[41]
    DIRECTION INPUT ;
    USE SIGNAL ;
    PORT
      LAYER M4 ;
        RECT  0 35.52 0.084 35.544 ;
    END
  END q1[41]
  PIN q1[42]
    DIRECTION INPUT ;
    USE SIGNAL ;
    PORT
      LAYER M4 ;
        RECT  0 35.664 0.084 35.688 ;
    END
  END q1[42]
  PIN q1[43]
    DIRECTION INPUT ;
    USE SIGNAL ;
    PORT
      LAYER M4 ;
        RECT  0 35.952 0.084 35.976 ;
    END
  END q1[43]
  PIN q1[44]
    DIRECTION INPUT ;
    USE SIGNAL ;
    PORT
      LAYER M4 ;
        RECT  0 36.048 0.084 36.072 ;
    END
  END q1[44]
  PIN q1[45]
    DIRECTION INPUT ;
    USE SIGNAL ;
    PORT
      LAYER M4 ;
        RECT  0 36.336 0.084 36.36 ;
    END
  END q1[45]
  PIN q1[46]
    DIRECTION INPUT ;
    USE SIGNAL ;
    PORT
      LAYER M4 ;
        RECT  0 36.72 0.084 36.744 ;
    END
  END q1[46]
  PIN q1[47]
    DIRECTION INPUT ;
    USE SIGNAL ;
    PORT
      LAYER M4 ;
        RECT  0 37.008 0.084 37.032 ;
    END
  END q1[47]
  PIN q1[4]
    DIRECTION INPUT ;
    USE SIGNAL ;
    PORT
      LAYER M4 ;
        RECT  0 36.864 0.084 36.888 ;
    END
  END q1[4]
  PIN q1[5]
    DIRECTION INPUT ;
    USE SIGNAL ;
    PORT
      LAYER M4 ;
        RECT  0 37.152 0.084 37.176 ;
    END
  END q1[5]
  PIN q1[6]
    DIRECTION INPUT ;
    USE SIGNAL ;
    PORT
      LAYER M4 ;
        RECT  0 37.296 0.084 37.32 ;
    END
  END q1[6]
  PIN q1[7]
    DIRECTION INPUT ;
    USE SIGNAL ;
    PORT
      LAYER M4 ;
        RECT  0 37.392 0.084 37.416 ;
    END
  END q1[7]
  PIN q1[8]
    DIRECTION INPUT ;
    USE SIGNAL ;
    PORT
      LAYER M4 ;
        RECT  0 37.536 0.084 37.56 ;
    END
  END q1[8]
  PIN q1[9]
    DIRECTION INPUT ;
    USE SIGNAL ;
    PORT
      LAYER M4 ;
        RECT  0 37.68 0.084 37.704 ;
    END
  END q1[9]
  PIN q2[0]
    DIRECTION INPUT ;
    USE SIGNAL ;
    PORT
      LAYER M4 ;
        RECT  0 29.328 0.084 29.352 ;
    END
  END q2[0]
  PIN q2[10]
    DIRECTION INPUT ;
    USE SIGNAL ;
    PORT
      LAYER M4 ;
        RECT  0 31.344 0.084 31.368 ;
    END
  END q2[10]
  PIN q2[11]
    DIRECTION INPUT ;
    USE SIGNAL ;
    PORT
      LAYER M4 ;
        RECT  0 31.488 0.084 31.512 ;
    END
  END q2[11]
  PIN q2[12]
    DIRECTION INPUT ;
    USE SIGNAL ;
    PORT
      LAYER M4 ;
        RECT  0 31.632 0.084 31.656 ;
    END
  END q2[12]
  PIN q2[13]
    DIRECTION INPUT ;
    USE SIGNAL ;
    PORT
      LAYER M4 ;
        RECT  0 31.776 0.084 31.8 ;
    END
  END q2[13]
  PIN q2[14]
    DIRECTION INPUT ;
    USE SIGNAL ;
    PORT
      LAYER M4 ;
        RECT  0 31.92 0.084 31.944 ;
    END
  END q2[14]
  PIN q2[15]
    DIRECTION INPUT ;
    USE SIGNAL ;
    PORT
      LAYER M4 ;
        RECT  0 32.016 0.084 32.04 ;
    END
  END q2[15]
  PIN q2[16]
    DIRECTION INPUT ;
    USE SIGNAL ;
    PORT
      LAYER M4 ;
        RECT  0 32.16 0.084 32.184 ;
    END
  END q2[16]
  PIN q2[17]
    DIRECTION INPUT ;
    USE SIGNAL ;
    PORT
      LAYER M4 ;
        RECT  0 32.304 0.084 32.328 ;
    END
  END q2[17]
  PIN q2[18]
    DIRECTION INPUT ;
    USE SIGNAL ;
    PORT
      LAYER M4 ;
        RECT  0 32.448 0.084 32.472 ;
    END
  END q2[18]
  PIN q2[19]
    DIRECTION INPUT ;
    USE SIGNAL ;
    PORT
      LAYER M4 ;
        RECT  0 32.592 0.084 32.616 ;
    END
  END q2[19]
  PIN q2[1]
    DIRECTION INPUT ;
    USE SIGNAL ;
    PORT
      LAYER M4 ;
        RECT  0 29.76 0.084 29.784 ;
    END
  END q2[1]
  PIN q2[20]
    DIRECTION INPUT ;
    USE SIGNAL ;
    PORT
      LAYER M4 ;
        RECT  0 32.688 0.084 32.712 ;
    END
  END q2[20]
  PIN q2[21]
    DIRECTION INPUT ;
    USE SIGNAL ;
    PORT
      LAYER M4 ;
        RECT  0 32.832 0.084 32.856 ;
    END
  END q2[21]
  PIN q2[22]
    DIRECTION INPUT ;
    USE SIGNAL ;
    PORT
      LAYER M4 ;
        RECT  0 32.976 0.084 33 ;
    END
  END q2[22]
  PIN q2[23]
    DIRECTION INPUT ;
    USE SIGNAL ;
    PORT
      LAYER M4 ;
        RECT  0 33.12 0.084 33.144 ;
    END
  END q2[23]
  PIN q2[24]
    DIRECTION INPUT ;
    USE SIGNAL ;
    PORT
      LAYER M4 ;
        RECT  0 33.264 0.084 33.288 ;
    END
  END q2[24]
  PIN q2[25]
    DIRECTION INPUT ;
    USE SIGNAL ;
    PORT
      LAYER M4 ;
        RECT  0 33.36 0.084 33.384 ;
    END
  END q2[25]
  PIN q2[26]
    DIRECTION INPUT ;
    USE SIGNAL ;
    PORT
      LAYER M4 ;
        RECT  0 33.504 0.084 33.528 ;
    END
  END q2[26]
  PIN q2[27]
    DIRECTION INPUT ;
    USE SIGNAL ;
    PORT
      LAYER M4 ;
        RECT  0 33.648 0.084 33.672 ;
    END
  END q2[27]
  PIN q2[28]
    DIRECTION INPUT ;
    USE SIGNAL ;
    PORT
      LAYER M4 ;
        RECT  0 33.792 0.084 33.816 ;
    END
  END q2[28]
  PIN q2[29]
    DIRECTION INPUT ;
    USE SIGNAL ;
    PORT
      LAYER M4 ;
        RECT  0 27.456 0.084 27.48 ;
    END
  END q2[29]
  PIN q2[2]
    DIRECTION INPUT ;
    USE SIGNAL ;
    PORT
      LAYER M4 ;
        RECT  0 30 0.084 30.024 ;
    END
  END q2[2]
  PIN q2[30]
    DIRECTION INPUT ;
    USE SIGNAL ;
    PORT
      LAYER M4 ;
        RECT  0 27.6 0.084 27.624 ;
    END
  END q2[30]
  PIN q2[31]
    DIRECTION INPUT ;
    USE SIGNAL ;
    PORT
      LAYER M4 ;
        RECT  0 27.744 0.084 27.768 ;
    END
  END q2[31]
  PIN q2[32]
    DIRECTION INPUT ;
    USE SIGNAL ;
    PORT
      LAYER M4 ;
        RECT  0 27.888 0.084 27.912 ;
    END
  END q2[32]
  PIN q2[33]
    DIRECTION INPUT ;
    USE SIGNAL ;
    PORT
      LAYER M4 ;
        RECT  0 27.984 0.084 28.008 ;
    END
  END q2[33]
  PIN q2[34]
    DIRECTION INPUT ;
    USE SIGNAL ;
    PORT
      LAYER M4 ;
        RECT  0 28.128 0.084 28.152 ;
    END
  END q2[34]
  PIN q2[35]
    DIRECTION INPUT ;
    USE SIGNAL ;
    PORT
      LAYER M4 ;
        RECT  0 28.272 0.084 28.296 ;
    END
  END q2[35]
  PIN q2[36]
    DIRECTION INPUT ;
    USE SIGNAL ;
    PORT
      LAYER M4 ;
        RECT  0 28.416 0.084 28.44 ;
    END
  END q2[36]
  PIN q2[37]
    DIRECTION INPUT ;
    USE SIGNAL ;
    PORT
      LAYER M4 ;
        RECT  0 28.56 0.084 28.584 ;
    END
  END q2[37]
  PIN q2[38]
    DIRECTION INPUT ;
    USE SIGNAL ;
    PORT
      LAYER M4 ;
        RECT  0 28.656 0.084 28.68 ;
    END
  END q2[38]
  PIN q2[39]
    DIRECTION INPUT ;
    USE SIGNAL ;
    PORT
      LAYER M4 ;
        RECT  0 28.8 0.084 28.824 ;
    END
  END q2[39]
  PIN q2[3]
    DIRECTION INPUT ;
    USE SIGNAL ;
    PORT
      LAYER M4 ;
        RECT  0 30.144 0.084 30.168 ;
    END
  END q2[3]
  PIN q2[40]
    DIRECTION INPUT ;
    USE SIGNAL ;
    PORT
      LAYER M4 ;
        RECT  0 28.944 0.084 28.968 ;
    END
  END q2[40]
  PIN q2[41]
    DIRECTION INPUT ;
    USE SIGNAL ;
    PORT
      LAYER M4 ;
        RECT  0 29.088 0.084 29.112 ;
    END
  END q2[41]
  PIN q2[42]
    DIRECTION INPUT ;
    USE SIGNAL ;
    PORT
      LAYER M4 ;
        RECT  0 29.232 0.084 29.256 ;
    END
  END q2[42]
  PIN q2[43]
    DIRECTION INPUT ;
    USE SIGNAL ;
    PORT
      LAYER M4 ;
        RECT  0 29.472 0.084 29.496 ;
    END
  END q2[43]
  PIN q2[44]
    DIRECTION INPUT ;
    USE SIGNAL ;
    PORT
      LAYER M4 ;
        RECT  0 29.616 0.084 29.64 ;
    END
  END q2[44]
  PIN q2[45]
    DIRECTION INPUT ;
    USE SIGNAL ;
    PORT
      LAYER M4 ;
        RECT  0 29.904 0.084 29.928 ;
    END
  END q2[45]
  PIN q2[46]
    DIRECTION INPUT ;
    USE SIGNAL ;
    PORT
      LAYER M4 ;
        RECT  0 30.288 0.084 30.312 ;
    END
  END q2[46]
  PIN q2[47]
    DIRECTION INPUT ;
    USE SIGNAL ;
    PORT
      LAYER M4 ;
        RECT  0 30.576 0.084 30.6 ;
    END
  END q2[47]
  PIN q2[4]
    DIRECTION INPUT ;
    USE SIGNAL ;
    PORT
      LAYER M4 ;
        RECT  0 30.432 0.084 30.456 ;
    END
  END q2[4]
  PIN q2[5]
    DIRECTION INPUT ;
    USE SIGNAL ;
    PORT
      LAYER M4 ;
        RECT  0 30.672 0.084 30.696 ;
    END
  END q2[5]
  PIN q2[6]
    DIRECTION INPUT ;
    USE SIGNAL ;
    PORT
      LAYER M4 ;
        RECT  0 30.816 0.084 30.84 ;
    END
  END q2[6]
  PIN q2[7]
    DIRECTION INPUT ;
    USE SIGNAL ;
    PORT
      LAYER M4 ;
        RECT  0 30.96 0.084 30.984 ;
    END
  END q2[7]
  PIN q2[8]
    DIRECTION INPUT ;
    USE SIGNAL ;
    PORT
      LAYER M4 ;
        RECT  0 31.104 0.084 31.128 ;
    END
  END q2[8]
  PIN q2[9]
    DIRECTION INPUT ;
    USE SIGNAL ;
    PORT
      LAYER M4 ;
        RECT  0 31.248 0.084 31.272 ;
    END
  END q2[9]
  PIN q3[0]
    DIRECTION INPUT ;
    USE SIGNAL ;
    PORT
      LAYER M4 ;
        RECT  0 22.224 0.084 22.248 ;
    END
  END q3[0]
  PIN q3[10]
    DIRECTION INPUT ;
    USE SIGNAL ;
    PORT
      LAYER M4 ;
        RECT  0 24.24 0.084 24.264 ;
    END
  END q3[10]
  PIN q3[11]
    DIRECTION INPUT ;
    USE SIGNAL ;
    PORT
      LAYER M4 ;
        RECT  0 24.384 0.084 24.408 ;
    END
  END q3[11]
  PIN q3[12]
    DIRECTION INPUT ;
    USE SIGNAL ;
    PORT
      LAYER M4 ;
        RECT  0 24.528 0.084 24.552 ;
    END
  END q3[12]
  PIN q3[13]
    DIRECTION INPUT ;
    USE SIGNAL ;
    PORT
      LAYER M4 ;
        RECT  0 24.624 0.084 24.648 ;
    END
  END q3[13]
  PIN q3[14]
    DIRECTION INPUT ;
    USE SIGNAL ;
    PORT
      LAYER M4 ;
        RECT  0 24.768 0.084 24.792 ;
    END
  END q3[14]
  PIN q3[15]
    DIRECTION INPUT ;
    USE SIGNAL ;
    PORT
      LAYER M4 ;
        RECT  0 24.912 0.084 24.936 ;
    END
  END q3[15]
  PIN q3[16]
    DIRECTION INPUT ;
    USE SIGNAL ;
    PORT
      LAYER M4 ;
        RECT  0 25.056 0.084 25.08 ;
    END
  END q3[16]
  PIN q3[17]
    DIRECTION INPUT ;
    USE SIGNAL ;
    PORT
      LAYER M4 ;
        RECT  0 25.2 0.084 25.224 ;
    END
  END q3[17]
  PIN q3[18]
    DIRECTION INPUT ;
    USE SIGNAL ;
    PORT
      LAYER M4 ;
        RECT  0 25.296 0.084 25.32 ;
    END
  END q3[18]
  PIN q3[19]
    DIRECTION INPUT ;
    USE SIGNAL ;
    PORT
      LAYER M4 ;
        RECT  0 25.44 0.084 25.464 ;
    END
  END q3[19]
  PIN q3[1]
    DIRECTION INPUT ;
    USE SIGNAL ;
    PORT
      LAYER M4 ;
        RECT  0 22.608 0.084 22.632 ;
    END
  END q3[1]
  PIN q3[20]
    DIRECTION INPUT ;
    USE SIGNAL ;
    PORT
      LAYER M4 ;
        RECT  0 25.584 0.084 25.608 ;
    END
  END q3[20]
  PIN q3[21]
    DIRECTION INPUT ;
    USE SIGNAL ;
    PORT
      LAYER M4 ;
        RECT  0 25.728 0.084 25.752 ;
    END
  END q3[21]
  PIN q3[22]
    DIRECTION INPUT ;
    USE SIGNAL ;
    PORT
      LAYER M4 ;
        RECT  0 25.872 0.084 25.896 ;
    END
  END q3[22]
  PIN q3[23]
    DIRECTION INPUT ;
    USE SIGNAL ;
    PORT
      LAYER M4 ;
        RECT  0 25.968 0.084 25.992 ;
    END
  END q3[23]
  PIN q3[24]
    DIRECTION INPUT ;
    USE SIGNAL ;
    PORT
      LAYER M4 ;
        RECT  0 26.112 0.084 26.136 ;
    END
  END q3[24]
  PIN q3[25]
    DIRECTION INPUT ;
    USE SIGNAL ;
    PORT
      LAYER M4 ;
        RECT  0 26.256 0.084 26.28 ;
    END
  END q3[25]
  PIN q3[26]
    DIRECTION INPUT ;
    USE SIGNAL ;
    PORT
      LAYER M4 ;
        RECT  0 26.4 0.084 26.424 ;
    END
  END q3[26]
  PIN q3[27]
    DIRECTION INPUT ;
    USE SIGNAL ;
    PORT
      LAYER M4 ;
        RECT  0 26.544 0.084 26.568 ;
    END
  END q3[27]
  PIN q3[28]
    DIRECTION INPUT ;
    USE SIGNAL ;
    PORT
      LAYER M4 ;
        RECT  0 26.64 0.084 26.664 ;
    END
  END q3[28]
  PIN q3[29]
    DIRECTION INPUT ;
    USE SIGNAL ;
    PORT
      LAYER M4 ;
        RECT  0 20.352 0.084 20.376 ;
    END
  END q3[29]
  PIN q3[2]
    DIRECTION INPUT ;
    USE SIGNAL ;
    PORT
      LAYER M4 ;
        RECT  0 22.896 0.084 22.92 ;
    END
  END q3[2]
  PIN q3[30]
    DIRECTION INPUT ;
    USE SIGNAL ;
    PORT
      LAYER M4 ;
        RECT  0 20.496 0.084 20.52 ;
    END
  END q3[30]
  PIN q3[31]
    DIRECTION INPUT ;
    USE SIGNAL ;
    PORT
      LAYER M4 ;
        RECT  0 20.592 0.084 20.616 ;
    END
  END q3[31]
  PIN q3[32]
    DIRECTION INPUT ;
    USE SIGNAL ;
    PORT
      LAYER M4 ;
        RECT  0 20.736 0.084 20.76 ;
    END
  END q3[32]
  PIN q3[33]
    DIRECTION INPUT ;
    USE SIGNAL ;
    PORT
      LAYER M4 ;
        RECT  0 20.88 0.084 20.904 ;
    END
  END q3[33]
  PIN q3[34]
    DIRECTION INPUT ;
    USE SIGNAL ;
    PORT
      LAYER M4 ;
        RECT  0 21.024 0.084 21.048 ;
    END
  END q3[34]
  PIN q3[35]
    DIRECTION INPUT ;
    USE SIGNAL ;
    PORT
      LAYER M4 ;
        RECT  0 21.168 0.084 21.192 ;
    END
  END q3[35]
  PIN q3[36]
    DIRECTION INPUT ;
    USE SIGNAL ;
    PORT
      LAYER M4 ;
        RECT  0 21.264 0.084 21.288 ;
    END
  END q3[36]
  PIN q3[37]
    DIRECTION INPUT ;
    USE SIGNAL ;
    PORT
      LAYER M4 ;
        RECT  0 21.408 0.084 21.432 ;
    END
  END q3[37]
  PIN q3[38]
    DIRECTION INPUT ;
    USE SIGNAL ;
    PORT
      LAYER M4 ;
        RECT  0 21.552 0.084 21.576 ;
    END
  END q3[38]
  PIN q3[39]
    DIRECTION INPUT ;
    USE SIGNAL ;
    PORT
      LAYER M4 ;
        RECT  0 21.696 0.084 21.72 ;
    END
  END q3[39]
  PIN q3[3]
    DIRECTION INPUT ;
    USE SIGNAL ;
    PORT
      LAYER M4 ;
        RECT  0 23.04 0.084 23.064 ;
    END
  END q3[3]
  PIN q3[40]
    DIRECTION INPUT ;
    USE SIGNAL ;
    PORT
      LAYER M4 ;
        RECT  0 21.84 0.084 21.864 ;
    END
  END q3[40]
  PIN q3[41]
    DIRECTION INPUT ;
    USE SIGNAL ;
    PORT
      LAYER M4 ;
        RECT  0 21.936 0.084 21.96 ;
    END
  END q3[41]
  PIN q3[42]
    DIRECTION INPUT ;
    USE SIGNAL ;
    PORT
      LAYER M4 ;
        RECT  0 22.08 0.084 22.104 ;
    END
  END q3[42]
  PIN q3[43]
    DIRECTION INPUT ;
    USE SIGNAL ;
    PORT
      LAYER M4 ;
        RECT  0 22.368 0.084 22.392 ;
    END
  END q3[43]
  PIN q3[44]
    DIRECTION INPUT ;
    USE SIGNAL ;
    PORT
      LAYER M4 ;
        RECT  0 22.512 0.084 22.536 ;
    END
  END q3[44]
  PIN q3[45]
    DIRECTION INPUT ;
    USE SIGNAL ;
    PORT
      LAYER M4 ;
        RECT  0 22.752 0.084 22.776 ;
    END
  END q3[45]
  PIN q3[46]
    DIRECTION INPUT ;
    USE SIGNAL ;
    PORT
      LAYER M4 ;
        RECT  0 23.184 0.084 23.208 ;
    END
  END q3[46]
  PIN q3[47]
    DIRECTION INPUT ;
    USE SIGNAL ;
    PORT
      LAYER M4 ;
        RECT  0 23.424 0.084 23.448 ;
    END
  END q3[47]
  PIN q3[4]
    DIRECTION INPUT ;
    USE SIGNAL ;
    PORT
      LAYER M4 ;
        RECT  0 23.28 0.084 23.304 ;
    END
  END q3[4]
  PIN q3[5]
    DIRECTION INPUT ;
    USE SIGNAL ;
    PORT
      LAYER M4 ;
        RECT  0 23.568 0.084 23.592 ;
    END
  END q3[5]
  PIN q3[6]
    DIRECTION INPUT ;
    USE SIGNAL ;
    PORT
      LAYER M4 ;
        RECT  0 23.712 0.084 23.736 ;
    END
  END q3[6]
  PIN q3[7]
    DIRECTION INPUT ;
    USE SIGNAL ;
    PORT
      LAYER M4 ;
        RECT  0 23.856 0.084 23.88 ;
    END
  END q3[7]
  PIN q3[8]
    DIRECTION INPUT ;
    USE SIGNAL ;
    PORT
      LAYER M4 ;
        RECT  0 23.952 0.084 23.976 ;
    END
  END q3[8]
  PIN q3[9]
    DIRECTION INPUT ;
    USE SIGNAL ;
    PORT
      LAYER M4 ;
        RECT  0 24.096 0.084 24.12 ;
    END
  END q3[9]
  PIN q4[0]
    DIRECTION INPUT ;
    USE SIGNAL ;
    PORT
      LAYER M4 ;
        RECT  0 15.792 0.084 15.816 ;
    END
  END q4[0]
  PIN q4[10]
    DIRECTION INPUT ;
    USE SIGNAL ;
    PORT
      LAYER M4 ;
        RECT  0 17.808 0.084 17.832 ;
    END
  END q4[10]
  PIN q4[11]
    DIRECTION INPUT ;
    USE SIGNAL ;
    PORT
      LAYER M4 ;
        RECT  0 17.904 0.084 17.928 ;
    END
  END q4[11]
  PIN q4[12]
    DIRECTION INPUT ;
    USE SIGNAL ;
    PORT
      LAYER M4 ;
        RECT  0 18.048 0.084 18.072 ;
    END
  END q4[12]
  PIN q4[13]
    DIRECTION INPUT ;
    USE SIGNAL ;
    PORT
      LAYER M4 ;
        RECT  0 18.192 0.084 18.216 ;
    END
  END q4[13]
  PIN q4[14]
    DIRECTION INPUT ;
    USE SIGNAL ;
    PORT
      LAYER M4 ;
        RECT  0 18.336 0.084 18.36 ;
    END
  END q4[14]
  PIN q4[15]
    DIRECTION INPUT ;
    USE SIGNAL ;
    PORT
      LAYER M4 ;
        RECT  0 18.48 0.084 18.504 ;
    END
  END q4[15]
  PIN q4[16]
    DIRECTION INPUT ;
    USE SIGNAL ;
    PORT
      LAYER M4 ;
        RECT  0 18.576 0.084 18.6 ;
    END
  END q4[16]
  PIN q4[17]
    DIRECTION INPUT ;
    USE SIGNAL ;
    PORT
      LAYER M4 ;
        RECT  0 18.72 0.084 18.744 ;
    END
  END q4[17]
  PIN q4[18]
    DIRECTION INPUT ;
    USE SIGNAL ;
    PORT
      LAYER M4 ;
        RECT  0 18.864 0.084 18.888 ;
    END
  END q4[18]
  PIN q4[19]
    DIRECTION INPUT ;
    USE SIGNAL ;
    PORT
      LAYER M4 ;
        RECT  0 19.008 0.084 19.032 ;
    END
  END q4[19]
  PIN q4[1]
    DIRECTION INPUT ;
    USE SIGNAL ;
    PORT
      LAYER M4 ;
        RECT  0 16.176 0.084 16.2 ;
    END
  END q4[1]
  PIN q4[20]
    DIRECTION INPUT ;
    USE SIGNAL ;
    PORT
      LAYER M4 ;
        RECT  0 19.152 0.084 19.176 ;
    END
  END q4[20]
  PIN q4[21]
    DIRECTION INPUT ;
    USE SIGNAL ;
    PORT
      LAYER M4 ;
        RECT  0 19.248 0.084 19.272 ;
    END
  END q4[21]
  PIN q4[22]
    DIRECTION INPUT ;
    USE SIGNAL ;
    PORT
      LAYER M4 ;
        RECT  0 19.392 0.084 19.416 ;
    END
  END q4[22]
  PIN q4[23]
    DIRECTION INPUT ;
    USE SIGNAL ;
    PORT
      LAYER M4 ;
        RECT  0 19.536 0.084 19.56 ;
    END
  END q4[23]
  PIN q4[24]
    DIRECTION INPUT ;
    USE SIGNAL ;
    PORT
      LAYER M4 ;
        RECT  0 19.68 0.084 19.704 ;
    END
  END q4[24]
  PIN q4[25]
    DIRECTION INPUT ;
    USE SIGNAL ;
    PORT
      LAYER M4 ;
        RECT  0 19.824 0.084 19.848 ;
    END
  END q4[25]
  PIN q4[26]
    DIRECTION INPUT ;
    USE SIGNAL ;
    PORT
      LAYER M4 ;
        RECT  0 19.92 0.084 19.944 ;
    END
  END q4[26]
  PIN q4[27]
    DIRECTION INPUT ;
    USE SIGNAL ;
    PORT
      LAYER M4 ;
        RECT  0 20.064 0.084 20.088 ;
    END
  END q4[27]
  PIN q4[28]
    DIRECTION INPUT ;
    USE SIGNAL ;
    PORT
      LAYER M4 ;
        RECT  0 20.208 0.084 20.232 ;
    END
  END q4[28]
  PIN q4[29]
    DIRECTION INPUT ;
    USE SIGNAL ;
    PORT
      LAYER M4 ;
        RECT  0 13.872 0.084 13.896 ;
    END
  END q4[29]
  PIN q4[2]
    DIRECTION INPUT ;
    USE SIGNAL ;
    PORT
      LAYER M4 ;
        RECT  0 16.464 0.084 16.488 ;
    END
  END q4[2]
  PIN q4[30]
    DIRECTION INPUT ;
    USE SIGNAL ;
    PORT
      LAYER M4 ;
        RECT  0 14.016 0.084 14.04 ;
    END
  END q4[30]
  PIN q4[31]
    DIRECTION INPUT ;
    USE SIGNAL ;
    PORT
      LAYER M4 ;
        RECT  0 14.16 0.084 14.184 ;
    END
  END q4[31]
  PIN q4[32]
    DIRECTION INPUT ;
    USE SIGNAL ;
    PORT
      LAYER M4 ;
        RECT  0 14.304 0.084 14.328 ;
    END
  END q4[32]
  PIN q4[33]
    DIRECTION INPUT ;
    USE SIGNAL ;
    PORT
      LAYER M4 ;
        RECT  0 14.448 0.084 14.472 ;
    END
  END q4[33]
  PIN q4[34]
    DIRECTION INPUT ;
    USE SIGNAL ;
    PORT
      LAYER M4 ;
        RECT  0 14.544 0.084 14.568 ;
    END
  END q4[34]
  PIN q4[35]
    DIRECTION INPUT ;
    USE SIGNAL ;
    PORT
      LAYER M4 ;
        RECT  0 14.688 0.084 14.712 ;
    END
  END q4[35]
  PIN q4[36]
    DIRECTION INPUT ;
    USE SIGNAL ;
    PORT
      LAYER M4 ;
        RECT  0 14.832 0.084 14.856 ;
    END
  END q4[36]
  PIN q4[37]
    DIRECTION INPUT ;
    USE SIGNAL ;
    PORT
      LAYER M4 ;
        RECT  0 14.976 0.084 15 ;
    END
  END q4[37]
  PIN q4[38]
    DIRECTION INPUT ;
    USE SIGNAL ;
    PORT
      LAYER M4 ;
        RECT  0 15.12 0.084 15.144 ;
    END
  END q4[38]
  PIN q4[39]
    DIRECTION INPUT ;
    USE SIGNAL ;
    PORT
      LAYER M4 ;
        RECT  0 15.216 0.084 15.24 ;
    END
  END q4[39]
  PIN q4[3]
    DIRECTION INPUT ;
    USE SIGNAL ;
    PORT
      LAYER M4 ;
        RECT  0 16.56 0.084 16.584 ;
    END
  END q4[3]
  PIN q4[40]
    DIRECTION INPUT ;
    USE SIGNAL ;
    PORT
      LAYER M4 ;
        RECT  0 15.36 0.084 15.384 ;
    END
  END q4[40]
  PIN q4[41]
    DIRECTION INPUT ;
    USE SIGNAL ;
    PORT
      LAYER M4 ;
        RECT  0 15.504 0.084 15.528 ;
    END
  END q4[41]
  PIN q4[42]
    DIRECTION INPUT ;
    USE SIGNAL ;
    PORT
      LAYER M4 ;
        RECT  0 15.648 0.084 15.672 ;
    END
  END q4[42]
  PIN q4[43]
    DIRECTION INPUT ;
    USE SIGNAL ;
    PORT
      LAYER M4 ;
        RECT  0 15.888 0.084 15.912 ;
    END
  END q4[43]
  PIN q4[44]
    DIRECTION INPUT ;
    USE SIGNAL ;
    PORT
      LAYER M4 ;
        RECT  0 16.032 0.084 16.056 ;
    END
  END q4[44]
  PIN q4[45]
    DIRECTION INPUT ;
    USE SIGNAL ;
    PORT
      LAYER M4 ;
        RECT  0 16.32 0.084 16.344 ;
    END
  END q4[45]
  PIN q4[46]
    DIRECTION INPUT ;
    USE SIGNAL ;
    PORT
      LAYER M4 ;
        RECT  0 16.704 0.084 16.728 ;
    END
  END q4[46]
  PIN q4[47]
    DIRECTION INPUT ;
    USE SIGNAL ;
    PORT
      LAYER M4 ;
        RECT  0 16.992 0.084 17.016 ;
    END
  END q4[47]
  PIN q4[4]
    DIRECTION INPUT ;
    USE SIGNAL ;
    PORT
      LAYER M4 ;
        RECT  0 16.848 0.084 16.872 ;
    END
  END q4[4]
  PIN q4[5]
    DIRECTION INPUT ;
    USE SIGNAL ;
    PORT
      LAYER M4 ;
        RECT  0 17.136 0.084 17.16 ;
    END
  END q4[5]
  PIN q4[6]
    DIRECTION INPUT ;
    USE SIGNAL ;
    PORT
      LAYER M4 ;
        RECT  0 17.232 0.084 17.256 ;
    END
  END q4[6]
  PIN q4[7]
    DIRECTION INPUT ;
    USE SIGNAL ;
    PORT
      LAYER M4 ;
        RECT  0 17.376 0.084 17.4 ;
    END
  END q4[7]
  PIN q4[8]
    DIRECTION INPUT ;
    USE SIGNAL ;
    PORT
      LAYER M4 ;
        RECT  0 17.52 0.084 17.544 ;
    END
  END q4[8]
  PIN q4[9]
    DIRECTION INPUT ;
    USE SIGNAL ;
    PORT
      LAYER M4 ;
        RECT  0 17.664 0.084 17.688 ;
    END
  END q4[9]
  PIN q5[0]
    DIRECTION INPUT ;
    USE SIGNAL ;
    PORT
      LAYER M4 ;
        RECT  0 9.312 0.084 9.336 ;
    END
  END q5[0]
  PIN q5[10]
    DIRECTION INPUT ;
    USE SIGNAL ;
    PORT
      LAYER M4 ;
        RECT  0 11.328 0.084 11.352 ;
    END
  END q5[10]
  PIN q5[11]
    DIRECTION INPUT ;
    USE SIGNAL ;
    PORT
      LAYER M4 ;
        RECT  0 11.472 0.084 11.496 ;
    END
  END q5[11]
  PIN q5[12]
    DIRECTION INPUT ;
    USE SIGNAL ;
    PORT
      LAYER M4 ;
        RECT  0 11.616 0.084 11.64 ;
    END
  END q5[12]
  PIN q5[13]
    DIRECTION INPUT ;
    USE SIGNAL ;
    PORT
      LAYER M4 ;
        RECT  0 11.76 0.084 11.784 ;
    END
  END q5[13]
  PIN q5[14]
    DIRECTION INPUT ;
    USE SIGNAL ;
    PORT
      LAYER M4 ;
        RECT  0 11.856 0.084 11.88 ;
    END
  END q5[14]
  PIN q5[15]
    DIRECTION INPUT ;
    USE SIGNAL ;
    PORT
      LAYER M4 ;
        RECT  0 12 0.084 12.024 ;
    END
  END q5[15]
  PIN q5[16]
    DIRECTION INPUT ;
    USE SIGNAL ;
    PORT
      LAYER M4 ;
        RECT  0 12.144 0.084 12.168 ;
    END
  END q5[16]
  PIN q5[17]
    DIRECTION INPUT ;
    USE SIGNAL ;
    PORT
      LAYER M4 ;
        RECT  0 12.288 0.084 12.312 ;
    END
  END q5[17]
  PIN q5[18]
    DIRECTION INPUT ;
    USE SIGNAL ;
    PORT
      LAYER M4 ;
        RECT  0 12.432 0.084 12.456 ;
    END
  END q5[18]
  PIN q5[19]
    DIRECTION INPUT ;
    USE SIGNAL ;
    PORT
      LAYER M4 ;
        RECT  0 12.528 0.084 12.552 ;
    END
  END q5[19]
  PIN q5[1]
    DIRECTION INPUT ;
    USE SIGNAL ;
    PORT
      LAYER M4 ;
        RECT  0 9.744 0.084 9.768 ;
    END
  END q5[1]
  PIN q5[20]
    DIRECTION INPUT ;
    USE SIGNAL ;
    PORT
      LAYER M4 ;
        RECT  0 12.672 0.084 12.696 ;
    END
  END q5[20]
  PIN q5[21]
    DIRECTION INPUT ;
    USE SIGNAL ;
    PORT
      LAYER M4 ;
        RECT  0 12.816 0.084 12.84 ;
    END
  END q5[21]
  PIN q5[22]
    DIRECTION INPUT ;
    USE SIGNAL ;
    PORT
      LAYER M4 ;
        RECT  0 12.96 0.084 12.984 ;
    END
  END q5[22]
  PIN q5[23]
    DIRECTION INPUT ;
    USE SIGNAL ;
    PORT
      LAYER M4 ;
        RECT  0 13.104 0.084 13.128 ;
    END
  END q5[23]
  PIN q5[24]
    DIRECTION INPUT ;
    USE SIGNAL ;
    PORT
      LAYER M4 ;
        RECT  0 13.2 0.084 13.224 ;
    END
  END q5[24]
  PIN q5[25]
    DIRECTION INPUT ;
    USE SIGNAL ;
    PORT
      LAYER M4 ;
        RECT  0 13.344 0.084 13.368 ;
    END
  END q5[25]
  PIN q5[26]
    DIRECTION INPUT ;
    USE SIGNAL ;
    PORT
      LAYER M4 ;
        RECT  0 13.488 0.084 13.512 ;
    END
  END q5[26]
  PIN q5[27]
    DIRECTION INPUT ;
    USE SIGNAL ;
    PORT
      LAYER M4 ;
        RECT  0 13.632 0.084 13.656 ;
    END
  END q5[27]
  PIN q5[28]
    DIRECTION INPUT ;
    USE SIGNAL ;
    PORT
      LAYER M4 ;
        RECT  0 13.776 0.084 13.8 ;
    END
  END q5[28]
  PIN q5[29]
    DIRECTION INPUT ;
    USE SIGNAL ;
    PORT
      LAYER M4 ;
        RECT  0 7.44 0.084 7.464 ;
    END
  END q5[29]
  PIN q5[2]
    DIRECTION INPUT ;
    USE SIGNAL ;
    PORT
      LAYER M4 ;
        RECT  0 9.984 0.084 10.008 ;
    END
  END q5[2]
  PIN q5[30]
    DIRECTION INPUT ;
    USE SIGNAL ;
    PORT
      LAYER M4 ;
        RECT  0 7.584 0.084 7.608 ;
    END
  END q5[30]
  PIN q5[31]
    DIRECTION INPUT ;
    USE SIGNAL ;
    PORT
      LAYER M4 ;
        RECT  0 7.728 0.084 7.752 ;
    END
  END q5[31]
  PIN q5[32]
    DIRECTION INPUT ;
    USE SIGNAL ;
    PORT
      LAYER M4 ;
        RECT  0 7.824 0.084 7.848 ;
    END
  END q5[32]
  PIN q5[33]
    DIRECTION INPUT ;
    USE SIGNAL ;
    PORT
      LAYER M4 ;
        RECT  0 7.968 0.084 7.992 ;
    END
  END q5[33]
  PIN q5[34]
    DIRECTION INPUT ;
    USE SIGNAL ;
    PORT
      LAYER M4 ;
        RECT  0 8.112 0.084 8.136 ;
    END
  END q5[34]
  PIN q5[35]
    DIRECTION INPUT ;
    USE SIGNAL ;
    PORT
      LAYER M4 ;
        RECT  0 8.256 0.084 8.28 ;
    END
  END q5[35]
  PIN q5[36]
    DIRECTION INPUT ;
    USE SIGNAL ;
    PORT
      LAYER M4 ;
        RECT  0 8.4 0.084 8.424 ;
    END
  END q5[36]
  PIN q5[37]
    DIRECTION INPUT ;
    USE SIGNAL ;
    PORT
      LAYER M4 ;
        RECT  0 8.496 0.084 8.52 ;
    END
  END q5[37]
  PIN q5[38]
    DIRECTION INPUT ;
    USE SIGNAL ;
    PORT
      LAYER M4 ;
        RECT  0 8.64 0.084 8.664 ;
    END
  END q5[38]
  PIN q5[39]
    DIRECTION INPUT ;
    USE SIGNAL ;
    PORT
      LAYER M4 ;
        RECT  0 8.784 0.084 8.808 ;
    END
  END q5[39]
  PIN q5[3]
    DIRECTION INPUT ;
    USE SIGNAL ;
    PORT
      LAYER M4 ;
        RECT  0 10.128 0.084 10.152 ;
    END
  END q5[3]
  PIN q5[40]
    DIRECTION INPUT ;
    USE SIGNAL ;
    PORT
      LAYER M4 ;
        RECT  0 8.928 0.084 8.952 ;
    END
  END q5[40]
  PIN q5[41]
    DIRECTION INPUT ;
    USE SIGNAL ;
    PORT
      LAYER M4 ;
        RECT  0 9.072 0.084 9.096 ;
    END
  END q5[41]
  PIN q5[42]
    DIRECTION INPUT ;
    USE SIGNAL ;
    PORT
      LAYER M4 ;
        RECT  0 9.168 0.084 9.192 ;
    END
  END q5[42]
  PIN q5[43]
    DIRECTION INPUT ;
    USE SIGNAL ;
    PORT
      LAYER M4 ;
        RECT  0 9.456 0.084 9.48 ;
    END
  END q5[43]
  PIN q5[44]
    DIRECTION INPUT ;
    USE SIGNAL ;
    PORT
      LAYER M4 ;
        RECT  0 9.6 0.084 9.624 ;
    END
  END q5[44]
  PIN q5[45]
    DIRECTION INPUT ;
    USE SIGNAL ;
    PORT
      LAYER M4 ;
        RECT  0 9.84 0.084 9.864 ;
    END
  END q5[45]
  PIN q5[46]
    DIRECTION INPUT ;
    USE SIGNAL ;
    PORT
      LAYER M4 ;
        RECT  0 10.272 0.084 10.296 ;
    END
  END q5[46]
  PIN q5[47]
    DIRECTION INPUT ;
    USE SIGNAL ;
    PORT
      LAYER M4 ;
        RECT  0 10.512 0.084 10.536 ;
    END
  END q5[47]
  PIN q5[4]
    DIRECTION INPUT ;
    USE SIGNAL ;
    PORT
      LAYER M4 ;
        RECT  0 10.416 0.084 10.44 ;
    END
  END q5[4]
  PIN q5[5]
    DIRECTION INPUT ;
    USE SIGNAL ;
    PORT
      LAYER M4 ;
        RECT  0 10.656 0.084 10.68 ;
    END
  END q5[5]
  PIN q5[6]
    DIRECTION INPUT ;
    USE SIGNAL ;
    PORT
      LAYER M4 ;
        RECT  0 10.8 0.084 10.824 ;
    END
  END q5[6]
  PIN q5[7]
    DIRECTION INPUT ;
    USE SIGNAL ;
    PORT
      LAYER M4 ;
        RECT  0 10.944 0.084 10.968 ;
    END
  END q5[7]
  PIN q5[8]
    DIRECTION INPUT ;
    USE SIGNAL ;
    PORT
      LAYER M4 ;
        RECT  0 11.088 0.084 11.112 ;
    END
  END q5[8]
  PIN q5[9]
    DIRECTION INPUT ;
    USE SIGNAL ;
    PORT
      LAYER M4 ;
        RECT  0 11.184 0.084 11.208 ;
    END
  END q5[9]
  PIN q6[0]
    DIRECTION INPUT ;
    USE SIGNAL ;
    PORT
      LAYER M4 ;
        RECT  0 2.88 0.084 2.904 ;
    END
  END q6[0]
  PIN q6[10]
    DIRECTION INPUT ;
    USE SIGNAL ;
    PORT
      LAYER M4 ;
        RECT  0 4.896 0.084 4.92 ;
    END
  END q6[10]
  PIN q6[11]
    DIRECTION INPUT ;
    USE SIGNAL ;
    PORT
      LAYER M4 ;
        RECT  0 5.04 0.084 5.064 ;
    END
  END q6[11]
  PIN q6[12]
    DIRECTION INPUT ;
    USE SIGNAL ;
    PORT
      LAYER M4 ;
        RECT  0 5.136 0.084 5.16 ;
    END
  END q6[12]
  PIN q6[13]
    DIRECTION INPUT ;
    USE SIGNAL ;
    PORT
      LAYER M4 ;
        RECT  0 5.28 0.084 5.304 ;
    END
  END q6[13]
  PIN q6[14]
    DIRECTION INPUT ;
    USE SIGNAL ;
    PORT
      LAYER M4 ;
        RECT  0 5.424 0.084 5.448 ;
    END
  END q6[14]
  PIN q6[15]
    DIRECTION INPUT ;
    USE SIGNAL ;
    PORT
      LAYER M4 ;
        RECT  0 5.568 0.084 5.592 ;
    END
  END q6[15]
  PIN q6[16]
    DIRECTION INPUT ;
    USE SIGNAL ;
    PORT
      LAYER M4 ;
        RECT  0 5.712 0.084 5.736 ;
    END
  END q6[16]
  PIN q6[17]
    DIRECTION INPUT ;
    USE SIGNAL ;
    PORT
      LAYER M4 ;
        RECT  0 5.808 0.084 5.832 ;
    END
  END q6[17]
  PIN q6[18]
    DIRECTION INPUT ;
    USE SIGNAL ;
    PORT
      LAYER M4 ;
        RECT  0 5.952 0.084 5.976 ;
    END
  END q6[18]
  PIN q6[19]
    DIRECTION INPUT ;
    USE SIGNAL ;
    PORT
      LAYER M4 ;
        RECT  0 6.096 0.084 6.12 ;
    END
  END q6[19]
  PIN q6[1]
    DIRECTION INPUT ;
    USE SIGNAL ;
    PORT
      LAYER M4 ;
        RECT  0 3.264 0.084 3.288 ;
    END
  END q6[1]
  PIN q6[20]
    DIRECTION INPUT ;
    USE SIGNAL ;
    PORT
      LAYER M4 ;
        RECT  0 6.24 0.084 6.264 ;
    END
  END q6[20]
  PIN q6[21]
    DIRECTION INPUT ;
    USE SIGNAL ;
    PORT
      LAYER M4 ;
        RECT  0 6.384 0.084 6.408 ;
    END
  END q6[21]
  PIN q6[22]
    DIRECTION INPUT ;
    USE SIGNAL ;
    PORT
      LAYER M4 ;
        RECT  0 6.48 0.084 6.504 ;
    END
  END q6[22]
  PIN q6[23]
    DIRECTION INPUT ;
    USE SIGNAL ;
    PORT
      LAYER M4 ;
        RECT  0 6.624 0.084 6.648 ;
    END
  END q6[23]
  PIN q6[24]
    DIRECTION INPUT ;
    USE SIGNAL ;
    PORT
      LAYER M4 ;
        RECT  0 6.768 0.084 6.792 ;
    END
  END q6[24]
  PIN q6[25]
    DIRECTION INPUT ;
    USE SIGNAL ;
    PORT
      LAYER M4 ;
        RECT  0 6.912 0.084 6.936 ;
    END
  END q6[25]
  PIN q6[26]
    DIRECTION INPUT ;
    USE SIGNAL ;
    PORT
      LAYER M4 ;
        RECT  0 7.056 0.084 7.08 ;
    END
  END q6[26]
  PIN q6[27]
    DIRECTION INPUT ;
    USE SIGNAL ;
    PORT
      LAYER M4 ;
        RECT  0 7.152 0.084 7.176 ;
    END
  END q6[27]
  PIN q6[28]
    DIRECTION INPUT ;
    USE SIGNAL ;
    PORT
      LAYER M4 ;
        RECT  0 7.296 0.084 7.32 ;
    END
  END q6[28]
  PIN q6[29]
    DIRECTION INPUT ;
    USE SIGNAL ;
    PORT
      LAYER M4 ;
        RECT  0 1.008 0.084 1.032 ;
    END
  END q6[29]
  PIN q6[2]
    DIRECTION INPUT ;
    USE SIGNAL ;
    PORT
      LAYER M4 ;
        RECT  0 3.552 0.084 3.576 ;
    END
  END q6[2]
  PIN q6[30]
    DIRECTION INPUT ;
    USE SIGNAL ;
    PORT
      LAYER M4 ;
        RECT  0 1.104 0.084 1.128 ;
    END
  END q6[30]
  PIN q6[31]
    DIRECTION INPUT ;
    USE SIGNAL ;
    PORT
      LAYER M4 ;
        RECT  0 1.248 0.084 1.272 ;
    END
  END q6[31]
  PIN q6[32]
    DIRECTION INPUT ;
    USE SIGNAL ;
    PORT
      LAYER M4 ;
        RECT  0 1.392 0.084 1.416 ;
    END
  END q6[32]
  PIN q6[33]
    DIRECTION INPUT ;
    USE SIGNAL ;
    PORT
      LAYER M4 ;
        RECT  0 1.536 0.084 1.56 ;
    END
  END q6[33]
  PIN q6[34]
    DIRECTION INPUT ;
    USE SIGNAL ;
    PORT
      LAYER M4 ;
        RECT  0 1.68 0.084 1.704 ;
    END
  END q6[34]
  PIN q6[35]
    DIRECTION INPUT ;
    USE SIGNAL ;
    PORT
      LAYER M4 ;
        RECT  0 1.776 0.084 1.8 ;
    END
  END q6[35]
  PIN q6[36]
    DIRECTION INPUT ;
    USE SIGNAL ;
    PORT
      LAYER M4 ;
        RECT  0 1.92 0.084 1.944 ;
    END
  END q6[36]
  PIN q6[37]
    DIRECTION INPUT ;
    USE SIGNAL ;
    PORT
      LAYER M4 ;
        RECT  0 2.064 0.084 2.088 ;
    END
  END q6[37]
  PIN q6[38]
    DIRECTION INPUT ;
    USE SIGNAL ;
    PORT
      LAYER M4 ;
        RECT  0 2.208 0.084 2.232 ;
    END
  END q6[38]
  PIN q6[39]
    DIRECTION INPUT ;
    USE SIGNAL ;
    PORT
      LAYER M4 ;
        RECT  0 2.352 0.084 2.376 ;
    END
  END q6[39]
  PIN q6[3]
    DIRECTION INPUT ;
    USE SIGNAL ;
    PORT
      LAYER M4 ;
        RECT  0 3.696 0.084 3.72 ;
    END
  END q6[3]
  PIN q6[40]
    DIRECTION INPUT ;
    USE SIGNAL ;
    PORT
      LAYER M4 ;
        RECT  0 2.448 0.084 2.472 ;
    END
  END q6[40]
  PIN q6[41]
    DIRECTION INPUT ;
    USE SIGNAL ;
    PORT
      LAYER M4 ;
        RECT  0 2.592 0.084 2.616 ;
    END
  END q6[41]
  PIN q6[42]
    DIRECTION INPUT ;
    USE SIGNAL ;
    PORT
      LAYER M4 ;
        RECT  0 2.736 0.084 2.76 ;
    END
  END q6[42]
  PIN q6[43]
    DIRECTION INPUT ;
    USE SIGNAL ;
    PORT
      LAYER M4 ;
        RECT  0 3.024 0.084 3.048 ;
    END
  END q6[43]
  PIN q6[44]
    DIRECTION INPUT ;
    USE SIGNAL ;
    PORT
      LAYER M4 ;
        RECT  0 3.12 0.084 3.144 ;
    END
  END q6[44]
  PIN q6[45]
    DIRECTION INPUT ;
    USE SIGNAL ;
    PORT
      LAYER M4 ;
        RECT  0 3.408 0.084 3.432 ;
    END
  END q6[45]
  PIN q6[46]
    DIRECTION INPUT ;
    USE SIGNAL ;
    PORT
      LAYER M4 ;
        RECT  0 3.792 0.084 3.816 ;
    END
  END q6[46]
  PIN q6[47]
    DIRECTION INPUT ;
    USE SIGNAL ;
    PORT
      LAYER M4 ;
        RECT  0 4.08 0.084 4.104 ;
    END
  END q6[47]
  PIN q6[4]
    DIRECTION INPUT ;
    USE SIGNAL ;
    PORT
      LAYER M4 ;
        RECT  0 3.936 0.084 3.96 ;
    END
  END q6[4]
  PIN q6[5]
    DIRECTION INPUT ;
    USE SIGNAL ;
    PORT
      LAYER M4 ;
        RECT  0 4.224 0.084 4.248 ;
    END
  END q6[5]
  PIN q6[6]
    DIRECTION INPUT ;
    USE SIGNAL ;
    PORT
      LAYER M4 ;
        RECT  0 4.368 0.084 4.392 ;
    END
  END q6[6]
  PIN q6[7]
    DIRECTION INPUT ;
    USE SIGNAL ;
    PORT
      LAYER M4 ;
        RECT  0 4.464 0.084 4.488 ;
    END
  END q6[7]
  PIN q6[8]
    DIRECTION INPUT ;
    USE SIGNAL ;
    PORT
      LAYER M4 ;
        RECT  0 4.608 0.084 4.632 ;
    END
  END q6[8]
  PIN q6[9]
    DIRECTION INPUT ;
    USE SIGNAL ;
    PORT
      LAYER M4 ;
        RECT  0 4.752 0.084 4.776 ;
    END
  END q6[9]
  PIN rst_n[0]
    DIRECTION INPUT ;
    USE SIGNAL ;
    PORT
      LAYER M5 ;
        RECT  8.64 0 8.664 0.084 ;
    END
    PORT
      LAYER M5 ;
        RECT  8.64 0.016 8.664 1.763 ;
    END
  END rst_n[0]
  PIN st[0]
    DIRECTION OUTPUT ;
    USE SIGNAL ;
    PORT
      LAYER M4 ;
        RECT  17.196 35.616 17.28 35.64 ;
    END
    PORT
      LAYER M4 ;
        RECT  16.477 35.616 17.244 35.64 ;
    END
  END st[0]
  PIN st[1]
    DIRECTION OUTPUT ;
    USE SIGNAL ;
    PORT
      LAYER M4 ;
        RECT  17.196 37.776 17.28 37.8 ;
    END
    PORT
      LAYER M4 ;
        RECT  16.477 37.776 17.244 37.8 ;
    END
  END st[1]
  PIN VDD
    DIRECTION INOUT ;
    USE POWER ;
    PORT
      LAYER M5 ;
        RECT  13.392 2.151 13.512 49.689 ;
        RECT  10.692 2.151 10.812 49.689 ;
        RECT  7.992 2.151 8.112 49.689 ;
        RECT  5.292 2.151 5.412 49.689 ;
        RECT  2.592 2.151 2.712 49.689 ;
    END
  END VDD
  PIN VSS
    DIRECTION INOUT ;
    USE GROUND ;
    PORT
      LAYER M5 ;
        RECT  13.2 2.137 13.32 49.703 ;
        RECT  10.5 2.137 10.62 49.703 ;
        RECT  7.8 2.137 7.92 49.703 ;
        RECT  5.1 2.137 5.22 49.703 ;
        RECT  2.4 2.137 2.52 49.703 ;
    END
  END VSS
  # OT_OBS_CLOSED layer=M5 d_um=1.536 added=27
  OBS
    LAYER RVTN ;
     RECT  2.16 2.16 15.12 2.295 ;
     RECT  2.16 2.565 15.12 2.835 ;
     RECT  2.16 3.105 15.12 3.375 ;
     RECT  2.16 3.645 15.12 3.915 ;
     RECT  2.16 4.185 15.12 4.455 ;
     RECT  2.16 4.725 15.12 4.995 ;
     RECT  2.16 5.265 15.12 5.535 ;
     RECT  2.16 5.805 15.12 6.075 ;
     RECT  2.16 6.345 15.12 6.615 ;
     RECT  2.16 6.885 15.12 7.155 ;
     RECT  2.16 7.425 15.12 7.695 ;
     RECT  2.16 7.965 15.12 8.235 ;
     RECT  2.16 8.505 15.12 8.775 ;
     RECT  2.16 9.045 15.12 9.315 ;
     RECT  2.16 9.585 15.12 9.855 ;
     RECT  2.16 10.125 15.12 10.395 ;
     RECT  2.16 10.665 15.12 10.935 ;
     RECT  2.16 11.205 15.12 11.475 ;
     RECT  2.16 11.745 15.12 12.015 ;
     RECT  2.16 12.285 15.12 12.555 ;
     RECT  2.16 12.825 15.12 13.095 ;
     RECT  2.16 13.365 15.12 13.635 ;
     RECT  2.16 13.905 15.12 14.175 ;
     RECT  2.16 14.445 15.12 14.715 ;
     RECT  2.16 14.985 15.12 15.255 ;
     RECT  2.16 15.525 15.12 15.795 ;
     RECT  2.16 16.065 15.12 16.335 ;
     RECT  2.16 16.605 15.12 16.875 ;
     RECT  2.16 17.145 15.12 17.415 ;
     RECT  2.16 17.685 15.12 17.955 ;
     RECT  2.16 18.225 15.12 18.495 ;
     RECT  2.16 18.765 15.12 19.035 ;
     RECT  2.16 19.305 15.12 19.575 ;
     RECT  2.16 19.845 15.12 20.115 ;
     RECT  2.16 20.385 15.12 20.655 ;
     RECT  2.16 20.925 15.12 21.195 ;
     RECT  2.16 21.465 15.12 21.735 ;
     RECT  2.16 22.005 15.12 22.275 ;
     RECT  2.16 22.545 15.12 22.815 ;
     RECT  2.16 23.085 15.12 23.355 ;
     RECT  2.16 23.625 15.12 23.895 ;
     RECT  2.16 24.165 15.12 24.435 ;
     RECT  2.16 24.705 15.12 24.975 ;
     RECT  2.16 25.245 15.12 25.515 ;
     RECT  2.16 25.785 15.12 26.055 ;
     RECT  2.16 26.325 15.12 26.595 ;
     RECT  2.16 26.865 15.12 27.135 ;
     RECT  2.16 27.405 15.12 27.675 ;
     RECT  2.16 27.945 15.12 28.215 ;
     RECT  2.16 28.485 15.12 28.755 ;
     RECT  2.16 29.025 15.12 29.295 ;
     RECT  2.16 29.565 15.12 29.835 ;
     RECT  2.16 30.105 15.12 30.375 ;
     RECT  2.16 30.645 15.12 30.915 ;
     RECT  2.16 31.185 15.12 31.455 ;
     RECT  2.16 31.725 15.12 31.995 ;
     RECT  2.16 32.265 15.12 32.535 ;
     RECT  2.16 32.805 15.12 33.075 ;
     RECT  2.16 33.345 15.12 33.615 ;
     RECT  2.16 33.885 15.12 34.155 ;
     RECT  2.16 34.425 15.12 34.695 ;
     RECT  2.16 34.965 15.12 35.235 ;
     RECT  2.16 35.505 15.12 35.775 ;
     RECT  2.16 36.045 15.12 36.315 ;
     RECT  2.16 36.585 15.12 36.855 ;
     RECT  2.16 37.125 15.12 37.395 ;
     RECT  2.16 37.665 15.12 37.935 ;
     RECT  2.16 38.205 15.12 38.475 ;
     RECT  2.16 38.745 15.12 39.015 ;
     RECT  2.16 39.285 15.12 39.555 ;
     RECT  2.16 39.825 15.12 40.095 ;
     RECT  2.16 40.365 15.12 40.635 ;
     RECT  2.16 40.905 15.12 41.175 ;
     RECT  2.16 41.445 15.12 41.715 ;
     RECT  2.16 41.985 15.12 42.255 ;
     RECT  2.16 42.525 15.12 42.795 ;
     RECT  2.16 43.065 15.12 43.335 ;
     RECT  2.16 43.605 15.12 43.875 ;
     RECT  2.16 44.145 15.12 44.415 ;
     RECT  2.16 44.685 15.12 44.955 ;
     RECT  2.16 45.225 15.12 45.495 ;
     RECT  2.16 45.765 15.12 46.035 ;
     RECT  2.16 46.305 15.12 46.575 ;
     RECT  2.16 46.845 15.12 47.115 ;
     RECT  2.16 47.385 15.12 47.655 ;
     RECT  2.16 47.925 15.12 48.195 ;
     RECT  2.16 48.465 15.12 48.735 ;
     RECT  2.16 49.005 15.12 49.275 ;
     RECT  2.16 49.545 15.12 49.68 ;
    LAYER RVTP ;
     RECT  2.16 2.295 15.12 2.565 ;
     RECT  2.16 2.835 15.12 3.105 ;
     RECT  2.16 3.375 15.12 3.645 ;
     RECT  2.16 3.915 15.12 4.185 ;
     RECT  2.16 4.455 15.12 4.725 ;
     RECT  2.16 4.995 15.12 5.265 ;
     RECT  2.16 5.535 15.12 5.805 ;
     RECT  2.16 6.075 15.12 6.345 ;
     RECT  2.16 6.615 15.12 6.885 ;
     RECT  2.16 7.155 15.12 7.425 ;
     RECT  2.16 7.695 15.12 7.965 ;
     RECT  2.16 8.235 15.12 8.505 ;
     RECT  2.16 8.775 15.12 9.045 ;
     RECT  2.16 9.315 15.12 9.585 ;
     RECT  2.16 9.855 15.12 10.125 ;
     RECT  2.16 10.395 15.12 10.665 ;
     RECT  2.16 10.935 15.12 11.205 ;
     RECT  2.16 11.475 15.12 11.745 ;
     RECT  2.16 12.015 15.12 12.285 ;
     RECT  2.16 12.555 15.12 12.825 ;
     RECT  2.16 13.095 15.12 13.365 ;
     RECT  2.16 13.635 15.12 13.905 ;
     RECT  2.16 14.175 15.12 14.445 ;
     RECT  2.16 14.715 15.12 14.985 ;
     RECT  2.16 15.255 15.12 15.525 ;
     RECT  2.16 15.795 15.12 16.065 ;
     RECT  2.16 16.335 15.12 16.605 ;
     RECT  2.16 16.875 15.12 17.145 ;
     RECT  2.16 17.415 15.12 17.685 ;
     RECT  2.16 17.955 15.12 18.225 ;
     RECT  2.16 18.495 15.12 18.765 ;
     RECT  2.16 19.035 15.12 19.305 ;
     RECT  2.16 19.575 15.12 19.845 ;
     RECT  2.16 20.115 15.12 20.385 ;
     RECT  2.16 20.655 15.12 20.925 ;
     RECT  2.16 21.195 15.12 21.465 ;
     RECT  2.16 21.735 15.12 22.005 ;
     RECT  2.16 22.275 15.12 22.545 ;
     RECT  2.16 22.815 15.12 23.085 ;
     RECT  2.16 23.355 15.12 23.625 ;
     RECT  2.16 23.895 15.12 24.165 ;
     RECT  2.16 24.435 15.12 24.705 ;
     RECT  2.16 24.975 15.12 25.245 ;
     RECT  2.16 25.515 15.12 25.785 ;
     RECT  2.16 26.055 15.12 26.325 ;
     RECT  2.16 26.595 15.12 26.865 ;
     RECT  2.16 27.135 15.12 27.405 ;
     RECT  2.16 27.675 15.12 27.945 ;
     RECT  2.16 28.215 15.12 28.485 ;
     RECT  2.16 28.755 15.12 29.025 ;
     RECT  2.16 29.295 15.12 29.565 ;
     RECT  2.16 29.835 15.12 30.105 ;
     RECT  2.16 30.375 15.12 30.645 ;
     RECT  2.16 30.915 15.12 31.185 ;
     RECT  2.16 31.455 15.12 31.725 ;
     RECT  2.16 31.995 15.12 32.265 ;
     RECT  2.16 32.535 15.12 32.805 ;
     RECT  2.16 33.075 15.12 33.345 ;
     RECT  2.16 33.615 15.12 33.885 ;
     RECT  2.16 34.155 15.12 34.425 ;
     RECT  2.16 34.695 15.12 34.965 ;
     RECT  2.16 35.235 15.12 35.505 ;
     RECT  2.16 35.775 15.12 36.045 ;
     RECT  2.16 36.315 15.12 36.585 ;
     RECT  2.16 36.855 15.12 37.125 ;
     RECT  2.16 37.395 15.12 37.665 ;
     RECT  2.16 37.935 15.12 38.205 ;
     RECT  2.16 38.475 15.12 38.745 ;
     RECT  2.16 39.015 15.12 39.285 ;
     RECT  2.16 39.555 15.12 39.825 ;
     RECT  2.16 40.095 15.12 40.365 ;
     RECT  2.16 40.635 15.12 40.905 ;
     RECT  2.16 41.175 15.12 41.445 ;
     RECT  2.16 41.715 15.12 41.985 ;
     RECT  2.16 42.255 15.12 42.525 ;
     RECT  2.16 42.795 15.12 43.065 ;
     RECT  2.16 43.335 15.12 43.605 ;
     RECT  2.16 43.875 15.12 44.145 ;
     RECT  2.16 44.415 15.12 44.685 ;
     RECT  2.16 44.955 15.12 45.225 ;
     RECT  2.16 45.495 15.12 45.765 ;
     RECT  2.16 46.035 15.12 46.305 ;
     RECT  2.16 46.575 15.12 46.845 ;
     RECT  2.16 47.115 15.12 47.385 ;
     RECT  2.16 47.655 15.12 47.925 ;
     RECT  2.16 48.195 15.12 48.465 ;
     RECT  2.16 48.735 15.12 49.005 ;
     RECT  2.16 49.275 15.12 49.545 ;
    LAYER M1 ;
     RECT  2.16 2.151 15.12 49.689 ;
    LAYER M2 ;
     RECT  0.103 36.9 0.139 36.918 ;
     RECT  0.103 41.454 0.139 41.472 ;
     RECT  0.103 45.891 0.139 45.909 ;
     RECT  0.139 41.454 0.211 41.508 ;
     RECT  0.139 45.891 0.211 46.26 ;
     RECT  0.211 45.81 0.239 46.26 ;
     RECT  0.239 45.81 0.383 45.909 ;
     RECT  0.103 27.342 0.499 28.98 ;
     RECT  0.211 41.22 0.535 41.508 ;
     RECT  0.103 43.074 0.823 43.092 ;
     RECT  0.103 44.19 1.183 44.208 ;
     RECT  0.383 45.81 1.183 45.828 ;
     RECT  0.139 36.522 1.687 36.918 ;
     RECT  1.147 47.196 1.687 47.214 ;
     RECT  1.219 48.132 1.687 48.15 ;
     RECT  0.535 40.446 1.723 41.508 ;
     RECT  0.823 42.606 1.723 43.092 ;
     RECT  1.183 44.19 1.723 44.712 ;
     RECT  1.183 45.504 1.723 45.828 ;
     RECT  1.723 2.232 1.759 2.25 ;
     RECT  1.687 47.196 2.047 48.15 ;
     RECT  1.723 40.446 2.083 41.778 ;
     RECT  1.723 42.606 2.083 45.828 ;
     RECT  0.211 37.872 2.119 37.89 ;
     RECT  0.103 38.718 2.119 39.312 ;
     RECT  0.103 32.472 2.155 33.03 ;
     RECT  2.119 37.872 2.155 39.312 ;
     RECT  2.083 40.446 2.155 45.828 ;
     RECT  1.759 2.034 2.16 2.25 ;
     RECT  0.535 8.316 2.16 8.334 ;
     RECT  0.535 12.87 2.16 12.888 ;
     RECT  2.155 14.49 2.16 14.508 ;
     RECT  0.103 22.212 2.16 22.23 ;
     RECT  0.499 27.108 2.16 28.98 ;
     RECT  1.687 30.042 2.16 30.06 ;
     RECT  2.155 31.77 2.16 33.03 ;
     RECT  1.687 34.164 2.16 34.182 ;
     RECT  0.103 35.01 2.16 35.028 ;
     RECT  1.687 36.126 2.16 36.918 ;
     RECT  2.155 37.872 2.16 45.828 ;
     RECT  2.047 46.656 2.16 48.15 ;
     RECT  1.687 49.356 2.16 49.374 ;
     RECT  2.16 2.034 2.803 49.689 ;
     RECT  2.803 1.962 3.335 49.689 ;
     RECT  3.335 2.106 4.379 49.689 ;
     RECT  4.379 2.151 5.503 49.689 ;
     RECT  5.503 2.106 6.251 49.689 ;
     RECT  6.251 2.151 15.12 49.689 ;
     RECT  15.12 5.58 15.395 5.598 ;
     RECT  15.12 9.828 15.395 9.846 ;
     RECT  15.12 22.788 15.395 22.806 ;
     RECT  15.12 24.948 15.395 24.966 ;
     RECT  15.12 27.18 15.395 27.198 ;
     RECT  15.12 33.39 15.431 33.408 ;
     RECT  15.12 3.348 15.971 3.366 ;
     RECT  15.12 7.74 15.971 7.758 ;
     RECT  15.12 11.952 15.971 11.97 ;
     RECT  15.12 20.7 15.971 20.718 ;
     RECT  15.12 29.268 15.971 29.286 ;
     RECT  15.12 31.5 15.971 31.518 ;
     RECT  15.12 18.162 16.007 18.18 ;
     RECT  15.12 35.676 16.511 35.694 ;
     RECT  15.12 37.836 16.511 37.854 ;
     RECT  15.12 16.272 17.195 16.29 ;
    LAYER M3 ;
     RECT  1.728 1.003 1.746 1.099 ;
     RECT  1.728 1.099 1.782 1.387 ;
     RECT  2.736 1.243 2.754 1.387 ;
     RECT  1.728 1.387 2.754 1.957 ;
     RECT  3.6 1.915 3.618 1.957 ;
     RECT  4.392 2.011 4.41 2.101 ;
     RECT  5.76 2.059 5.778 2.101 ;
     RECT  4.356 2.101 4.41 2.143 ;
     RECT  5.508 2.101 6.246 2.143 ;
     RECT  1.728 1.957 3.618 2.191 ;
     RECT  4.356 2.143 6.246 2.191 ;
     RECT  1.728 2.191 6.246 2.255 ;
     RECT  2.196 2.255 6.246 2.371 ;
     RECT  7.02 2.191 7.038 2.371 ;
     RECT  7.815 2.143 7.905 2.371 ;
     RECT  8.82 1.723 8.838 2.371 ;
     RECT  2.196 2.371 7.905 2.413 ;
     RECT  10.515 2.143 10.605 2.413 ;
     RECT  13.215 2.143 13.305 2.413 ;
     RECT  10.515 2.413 10.797 2.569 ;
     RECT  8.82 2.371 9.018 2.641 ;
     RECT  2.196 2.413 8.097 2.731 ;
     RECT  8.82 2.641 9.342 2.731 ;
     RECT  0.144 1.963 0.162 2.765 ;
     RECT  10.515 2.569 11.142 3.001 ;
     RECT  10.515 3.001 11.286 3.181 ;
     RECT  2.196 2.731 9.342 3.271 ;
     RECT  2.196 3.271 9.45 3.335 ;
     RECT  15.948 3.211 15.966 3.371 ;
     RECT  13.215 2.413 13.497 3.379 ;
     RECT  14.616 3.451 14.634 3.569 ;
     RECT  12.924 3.379 13.497 3.613 ;
     RECT  12.636 3.613 13.497 3.649 ;
     RECT  2.304 3.335 9.45 3.721 ;
     RECT  10.188 3.181 11.286 3.721 ;
     RECT  14.832 3.721 14.85 3.875 ;
     RECT  0.144 3.787 0.162 3.917 ;
     RECT  2.304 3.721 11.286 4.117 ;
     RECT  12.06 3.649 13.497 4.117 ;
     RECT  2.304 4.117 13.497 4.363 ;
     RECT  2.268 4.363 13.497 4.487 ;
     RECT  0.144 5.419 0.162 5.549 ;
     RECT  15.372 5.371 15.39 5.603 ;
     RECT  2.304 4.487 13.497 5.873 ;
     RECT  2.304 5.873 12.438 5.947 ;
     RECT  2.268 5.947 12.438 6.035 ;
     RECT  2.268 6.035 11.286 7.385 ;
     RECT  12.168 6.035 12.438 7.429 ;
     RECT  15.948 7.531 15.966 7.763 ;
     RECT  2.304 7.385 11.286 7.771 ;
     RECT  12.024 7.429 12.438 7.771 ;
     RECT  0.144 8.107 0.162 8.237 ;
     RECT  0.54 8.311 0.558 8.669 ;
     RECT  13.215 5.873 13.497 9.391 ;
     RECT  15.372 9.691 15.39 9.851 ;
     RECT  13.215 9.391 14.022 9.931 ;
     RECT  13.215 9.931 14.238 10.049 ;
     RECT  13.215 10.049 14.202 10.229 ;
     RECT  2.304 7.771 12.438 10.795 ;
     RECT  2.268 10.795 12.438 10.967 ;
     RECT  13.215 10.229 14.022 11.173 ;
     RECT  2.304 10.967 12.438 11.821 ;
     RECT  13.215 11.173 14.202 11.821 ;
     RECT  2.304 11.821 14.274 11.939 ;
     RECT  15.948 11.851 15.966 11.975 ;
     RECT  0.144 11.851 0.162 11.981 ;
     RECT  2.304 11.939 14.202 12.029 ;
     RECT  13.176 12.029 14.202 12.077 ;
     RECT  2.304 12.029 12.438 12.955 ;
     RECT  0.54 12.865 0.558 13.133 ;
     RECT  2.268 12.955 12.438 13.325 ;
     RECT  13.215 12.077 14.202 13.945 ;
     RECT  2.304 13.325 12.438 13.981 ;
     RECT  13.215 13.945 14.85 13.981 ;
     RECT  2.304 13.981 14.85 14.045 ;
     RECT  0.144 14.011 0.162 14.141 ;
     RECT  2.304 14.045 14.202 14.443 ;
     RECT  2.16 14.443 14.202 14.513 ;
     RECT  2.304 14.513 14.202 15.643 ;
     RECT  2.268 15.643 14.202 16.028 ;
     RECT  0.144 15.835 0.162 16.061 ;
     RECT  17.172 16.171 17.19 16.295 ;
     RECT  2.304 16.028 14.202 17.755 ;
     RECT  0.18 17.659 0.198 17.789 ;
     RECT  2.268 17.755 14.202 17.803 ;
     RECT  2.196 17.803 14.202 18.185 ;
     RECT  15.984 18.157 16.002 18.365 ;
     RECT  0.144 19.531 0.162 19.661 ;
     RECT  15.948 20.491 15.966 20.723 ;
     RECT  2.304 18.185 14.202 20.731 ;
     RECT  2.304 20.731 14.274 20.921 ;
     RECT  2.304 20.921 14.202 22.603 ;
     RECT  2.232 22.603 14.202 22.811 ;
     RECT  15.372 22.651 15.39 22.811 ;
     RECT  0.108 22.207 0.126 23.213 ;
     RECT  2.304 22.811 14.202 23.707 ;
     RECT  2.268 23.707 14.202 24.619 ;
     RECT  2.196 24.619 14.202 24.701 ;
     RECT  15.372 24.811 15.39 24.971 ;
     RECT  2.304 24.701 14.202 25.051 ;
     RECT  0.144 24.619 0.162 25.085 ;
     RECT  2.304 25.051 14.346 25.169 ;
     RECT  0.18 25.195 0.342 25.325 ;
     RECT  1.26 25.195 1.278 25.325 ;
     RECT  0.18 25.325 0.198 25.421 ;
     RECT  0.144 25.963 0.162 26.093 ;
     RECT  1.152 26.347 1.17 26.573 ;
     RECT  2.304 25.169 14.202 26.825 ;
     RECT  0.108 26.635 0.126 27.103 ;
     RECT  15.372 26.971 15.39 27.203 ;
     RECT  0.108 27.103 0.558 27.629 ;
     RECT  2.34 26.825 14.202 27.715 ;
     RECT  0.108 27.629 0.522 27.917 ;
     RECT  2.304 27.715 14.202 28.171 ;
     RECT  2.088 28.171 14.202 28.211 ;
     RECT  2.268 28.211 14.202 28.453 ;
     RECT  15.948 29.131 15.966 29.291 ;
     RECT  2.268 28.453 14.238 29.371 ;
     RECT  0.108 27.917 0.126 29.501 ;
     RECT  1.152 29.323 1.17 29.597 ;
     RECT  2.268 29.371 14.274 30.037 ;
     RECT  1.692 30.037 14.274 30.451 ;
     RECT  15.948 31.291 15.966 31.523 ;
     RECT  0.324 31.483 0.342 32.011 ;
     RECT  0.18 32.011 0.342 32.045 ;
     RECT  0.18 32.045 0.198 32.141 ;
     RECT  1.692 30.451 14.49 32.141 ;
     RECT  2.16 32.141 14.49 32.717 ;
     RECT  2.196 32.717 14.49 33.305 ;
     RECT  15.408 33.385 15.426 33.485 ;
     RECT  0.108 32.467 0.126 33.821 ;
     RECT  2.232 33.305 14.49 33.961 ;
     RECT  1.152 34.075 1.17 34.159 ;
     RECT  2.232 33.961 14.526 34.159 ;
     RECT  1.152 34.159 14.526 34.205 ;
     RECT  1.692 34.205 14.526 34.771 ;
     RECT  1.692 34.771 14.598 35.311 ;
     RECT  0.108 35.005 0.126 35.549 ;
     RECT  16.488 35.611 16.506 35.699 ;
     RECT  1.692 35.311 14.778 35.735 ;
     RECT  1.692 35.735 14.562 36.235 ;
     RECT  1.26 36.235 14.562 36.365 ;
     RECT  0.144 36.235 0.162 36.895 ;
     RECT  1.692 36.365 14.562 37.705 ;
     RECT  1.692 37.705 14.598 37.741 ;
     RECT  16.488 37.771 16.506 37.859 ;
     RECT  0.108 36.895 0.162 37.867 ;
     RECT  1.692 37.741 14.778 38.551 ;
     RECT  1.692 38.551 14.994 38.741 ;
     RECT  0.108 37.867 0.234 39.019 ;
     RECT  1.692 38.741 14.562 39.055 ;
     RECT  1.656 39.055 14.562 39.353 ;
     RECT  1.656 39.353 14.418 40.261 ;
     RECT  0.108 39.019 0.558 40.397 ;
     RECT  1.656 40.261 14.49 40.405 ;
     RECT  1.656 40.405 14.922 40.829 ;
     RECT  1.656 40.829 14.778 40.865 ;
     RECT  0.324 40.397 0.558 40.945 ;
     RECT  1.656 40.865 14.346 40.945 ;
     RECT  0.324 40.945 14.346 41.179 ;
     RECT  0.18 41.179 14.346 41.357 ;
     RECT  0.18 41.357 0.234 41.449 ;
     RECT  1.152 41.357 14.346 41.597 ;
     RECT  1.224 41.597 14.346 42.025 ;
     RECT  1.224 42.025 14.562 42.331 ;
     RECT  1.224 42.331 14.994 42.449 ;
     RECT  0.108 41.449 0.234 42.601 ;
     RECT  1.224 42.449 14.562 42.601 ;
     RECT  0.108 42.601 14.562 43.259 ;
     RECT  0.108 43.259 14.202 44.311 ;
     RECT  0.108 44.311 14.238 44.617 ;
     RECT  0.108 44.617 14.31 44.717 ;
     RECT  0.144 44.717 14.31 44.761 ;
     RECT  0.144 44.761 14.778 44.987 ;
     RECT  0.144 44.987 14.238 45.739 ;
     RECT  0.108 45.739 14.238 45.914 ;
     RECT  0.144 45.914 14.238 46.301 ;
     RECT  0.828 46.301 14.238 46.337 ;
     RECT  0.828 46.337 14.202 47.131 ;
     RECT  0.144 47.131 14.202 47.191 ;
     RECT  0.144 47.191 14.598 47.309 ;
     RECT  0.144 47.309 14.202 47.789 ;
     RECT  0.828 47.789 14.202 47.933 ;
     RECT  1.152 47.933 14.202 48.605 ;
     RECT  1.98 48.605 14.202 48.811 ;
     RECT  1.152 48.605 1.17 49.133 ;
     RECT  1.98 48.811 14.382 49.343 ;
     RECT  1.98 49.343 13.497 49.351 ;
     RECT  1.692 49.351 13.497 49.421 ;
     RECT  2.376 49.421 13.497 49.427 ;
     RECT  2.376 49.427 13.305 49.469 ;
     RECT  11.448 49.469 13.305 49.505 ;
     RECT  2.415 49.469 10.605 49.517 ;
     RECT  2.415 49.517 3.33 49.541 ;
     RECT  4.356 49.517 10.605 49.541 ;
     RECT  12.528 49.505 13.305 49.541 ;
     RECT  14.364 49.343 14.382 49.541 ;
     RECT  4.356 49.541 9.162 49.565 ;
     RECT  9.972 49.541 10.605 49.565 ;
     RECT  4.356 49.565 6.39 49.577 ;
     RECT  8.964 49.565 9.162 49.577 ;
     RECT  10.008 49.565 10.605 49.577 ;
     RECT  11.448 49.505 11.466 49.577 ;
     RECT  4.86 49.577 6.39 49.613 ;
     RECT  7.308 49.565 8.19 49.613 ;
     RECT  2.415 49.541 2.934 49.697 ;
     RECT  7.308 49.613 7.905 49.697 ;
     RECT  10.515 49.577 10.605 49.697 ;
     RECT  13.215 49.541 13.305 49.697 ;
     RECT  4.86 49.613 5.526 49.805 ;
     RECT  8.964 49.577 9.018 49.805 ;
     RECT  4.86 49.805 4.878 49.853 ;
     RECT  8.964 49.805 8.982 50.141 ;
     RECT  2.556 49.697 2.934 50.189 ;
     RECT  7.308 49.697 7.326 50.189 ;
     RECT  2.916 50.189 2.934 50.717 ;
     RECT  2.772 51.547 2.79 51.725 ;
    LAYER M4 ;
     RECT  0.084 1.008 0.179 1.032 ;
     RECT  0.06 1.032 0.179 1.104 ;
     RECT  0.084 1.104 0.179 1.128 ;
     RECT  0.06 1.128 0.179 1.248 ;
     RECT  0.084 1.248 0.179 1.272 ;
     RECT  0.06 1.272 0.179 1.392 ;
     RECT  0.084 1.392 0.179 1.416 ;
     RECT  0.06 1.416 0.179 1.536 ;
     RECT  0.084 1.536 0.179 1.56 ;
     RECT  0.06 1.56 0.179 1.68 ;
     RECT  0.084 1.68 0.179 1.704 ;
     RECT  0.06 1.704 0.179 1.776 ;
     RECT  0.084 1.776 0.179 1.8 ;
     RECT  0.06 1.8 0.179 1.92 ;
     RECT  0.084 1.92 0.179 1.944 ;
     RECT  0.06 1.944 0.179 2.064 ;
     RECT  0.084 2.064 0.179 2.088 ;
     RECT  0.06 2.088 0.179 2.208 ;
     RECT  0.084 2.208 0.179 2.232 ;
     RECT  0.06 2.232 0.179 2.352 ;
     RECT  0.084 2.352 0.179 2.376 ;
     RECT  0.06 2.376 0.179 2.448 ;
     RECT  0.084 2.448 0.179 2.472 ;
     RECT  0.06 2.472 0.179 2.592 ;
     RECT  0.084 2.592 0.179 2.616 ;
     RECT  0.06 2.616 0.179 2.736 ;
     RECT  0.084 2.736 0.179 2.76 ;
     RECT  0.06 2.76 0.179 2.88 ;
     RECT  0.084 2.88 0.179 2.904 ;
     RECT  0.06 2.904 0.179 3.024 ;
     RECT  0.084 3.024 0.179 3.048 ;
     RECT  0.06 3.048 0.179 3.12 ;
     RECT  0.084 3.12 0.179 3.144 ;
     RECT  0.06 3.144 0.179 3.264 ;
     RECT  0.084 3.264 0.179 3.288 ;
     RECT  0.06 3.288 0.179 3.408 ;
     RECT  0.084 3.408 0.179 3.432 ;
     RECT  0.06 3.432 0.179 3.552 ;
     RECT  0.084 3.552 0.179 3.576 ;
     RECT  0.06 3.576 0.179 3.696 ;
     RECT  0.084 3.696 0.179 3.72 ;
     RECT  0.06 3.72 0.179 3.792 ;
     RECT  0.084 3.792 0.179 3.816 ;
     RECT  0.06 3.816 0.179 3.936 ;
     RECT  0.084 3.936 0.179 3.96 ;
     RECT  0.06 3.96 0.179 4.08 ;
     RECT  0.084 4.08 0.179 4.104 ;
     RECT  0.06 4.104 0.179 4.224 ;
     RECT  0.084 4.224 0.179 4.248 ;
     RECT  0.06 4.248 0.179 4.368 ;
     RECT  0.084 4.368 0.179 4.392 ;
     RECT  0.06 4.392 0.179 4.464 ;
     RECT  0.084 4.464 0.179 4.488 ;
     RECT  0.06 4.488 0.179 4.608 ;
     RECT  0.084 4.608 0.179 4.632 ;
     RECT  0.06 4.632 0.179 4.752 ;
     RECT  0.084 4.752 0.179 4.776 ;
     RECT  0.06 4.776 0.179 4.896 ;
     RECT  0.084 4.896 0.179 4.92 ;
     RECT  0.06 4.92 0.179 5.04 ;
     RECT  0.084 5.04 0.179 5.064 ;
     RECT  0.06 5.064 0.179 5.136 ;
     RECT  0.084 5.136 0.179 5.16 ;
     RECT  0.06 5.16 0.179 5.28 ;
     RECT  0.084 5.28 0.179 5.304 ;
     RECT  0.06 5.304 0.179 5.424 ;
     RECT  0.084 5.424 0.179 5.448 ;
     RECT  0.06 5.448 0.179 5.568 ;
     RECT  0.084 5.568 0.179 5.592 ;
     RECT  0.06 5.592 0.179 5.712 ;
     RECT  0.084 5.712 0.179 5.736 ;
     RECT  0.06 5.736 0.179 5.808 ;
     RECT  0.084 5.808 0.179 5.832 ;
     RECT  0.06 5.832 0.179 5.952 ;
     RECT  0.084 5.952 0.179 5.976 ;
     RECT  0.06 5.976 0.179 6.096 ;
     RECT  0.084 6.096 0.179 6.12 ;
     RECT  0.06 6.12 0.179 6.24 ;
     RECT  0.084 6.24 0.179 6.264 ;
     RECT  0.06 6.264 0.179 6.384 ;
     RECT  0.084 6.384 0.179 6.408 ;
     RECT  0.06 6.408 0.179 6.48 ;
     RECT  0.084 6.48 0.179 6.504 ;
     RECT  0.06 6.504 0.179 6.624 ;
     RECT  0.084 6.624 0.179 6.648 ;
     RECT  0.06 6.648 0.179 6.768 ;
     RECT  0.084 6.768 0.179 6.792 ;
     RECT  0.06 6.792 0.179 6.912 ;
     RECT  0.084 6.912 0.179 6.936 ;
     RECT  0.06 6.936 0.179 7.056 ;
     RECT  0.084 7.056 0.179 7.08 ;
     RECT  0.06 7.08 0.179 7.152 ;
     RECT  0.084 7.152 0.179 7.176 ;
     RECT  0.06 7.176 0.179 7.296 ;
     RECT  0.084 7.296 0.179 7.32 ;
     RECT  0.06 7.32 0.179 7.44 ;
     RECT  0.084 7.44 0.179 7.464 ;
     RECT  0.06 7.464 0.179 7.584 ;
     RECT  0.084 7.584 0.179 7.608 ;
     RECT  0.06 7.608 0.179 7.728 ;
     RECT  0.084 7.728 0.179 7.752 ;
     RECT  0.06 7.752 0.179 7.824 ;
     RECT  0.084 7.824 0.179 7.848 ;
     RECT  0.06 7.848 0.179 7.968 ;
     RECT  0.084 7.968 0.179 7.992 ;
     RECT  0.06 7.992 0.179 8.112 ;
     RECT  0.084 8.112 0.179 8.136 ;
     RECT  0.06 8.136 0.179 8.256 ;
     RECT  0.084 8.256 0.179 8.28 ;
     RECT  0.06 8.28 0.179 8.4 ;
     RECT  0.084 8.4 0.179 8.424 ;
     RECT  0.06 8.424 0.179 8.496 ;
     RECT  0.084 8.496 0.179 8.52 ;
     RECT  0.06 8.52 0.179 8.64 ;
     RECT  0.084 8.64 0.179 8.664 ;
     RECT  0.06 8.664 0.179 8.784 ;
     RECT  0.084 8.784 0.179 8.808 ;
     RECT  0.06 8.808 0.179 8.928 ;
     RECT  0.084 8.928 0.179 8.952 ;
     RECT  0.06 8.952 0.179 9.072 ;
     RECT  0.084 9.072 0.179 9.096 ;
     RECT  0.06 9.096 0.179 9.168 ;
     RECT  0.084 9.168 0.179 9.192 ;
     RECT  0.06 9.192 0.179 9.312 ;
     RECT  0.084 9.312 0.179 9.336 ;
     RECT  0.06 9.336 0.179 9.456 ;
     RECT  0.084 9.456 0.179 9.48 ;
     RECT  0.06 9.48 0.179 9.6 ;
     RECT  0.084 9.6 0.179 9.624 ;
     RECT  0.06 9.624 0.179 9.744 ;
     RECT  0.084 9.744 0.179 9.768 ;
     RECT  0.06 9.768 0.179 9.84 ;
     RECT  0.084 9.84 0.179 9.864 ;
     RECT  0.06 9.864 0.179 9.984 ;
     RECT  0.084 9.984 0.179 10.008 ;
     RECT  0.06 10.008 0.179 10.128 ;
     RECT  0.084 10.128 0.179 10.152 ;
     RECT  0.06 10.152 0.179 10.272 ;
     RECT  0.084 10.272 0.179 10.296 ;
     RECT  0.06 10.296 0.179 10.416 ;
     RECT  0.084 10.416 0.179 10.44 ;
     RECT  0.06 10.44 0.179 10.512 ;
     RECT  0.084 10.512 0.179 10.536 ;
     RECT  0.06 10.536 0.179 10.656 ;
     RECT  0.084 10.656 0.179 10.68 ;
     RECT  0.06 10.68 0.179 10.8 ;
     RECT  0.084 10.8 0.179 10.824 ;
     RECT  0.06 10.824 0.179 10.944 ;
     RECT  0.084 10.944 0.179 10.968 ;
     RECT  0.06 10.968 0.179 11.088 ;
     RECT  0.084 11.088 0.179 11.112 ;
     RECT  0.06 11.112 0.179 11.184 ;
     RECT  0.084 11.184 0.179 11.208 ;
     RECT  0.06 11.208 0.179 11.328 ;
     RECT  0.084 11.328 0.179 11.352 ;
     RECT  0.06 11.352 0.179 11.472 ;
     RECT  0.084 11.472 0.179 11.496 ;
     RECT  0.06 11.496 0.179 11.616 ;
     RECT  0.084 11.616 0.179 11.64 ;
     RECT  0.06 11.64 0.179 11.76 ;
     RECT  0.084 11.76 0.179 11.784 ;
     RECT  0.06 11.784 0.179 11.856 ;
     RECT  0.084 11.856 0.179 11.88 ;
     RECT  0.06 11.88 0.179 12 ;
     RECT  0.084 12 0.179 12.024 ;
     RECT  0.06 12.024 0.179 12.144 ;
     RECT  0.084 12.144 0.179 12.168 ;
     RECT  0.06 12.168 0.179 12.288 ;
     RECT  0.084 12.288 0.179 12.312 ;
     RECT  0.06 12.312 0.179 12.432 ;
     RECT  0.084 12.432 0.179 12.456 ;
     RECT  0.06 12.456 0.179 12.528 ;
     RECT  0.084 12.528 0.179 12.552 ;
     RECT  0.06 12.552 0.179 12.672 ;
     RECT  0.084 12.672 0.179 12.696 ;
     RECT  0.06 12.696 0.179 12.816 ;
     RECT  0.084 12.816 0.179 12.84 ;
     RECT  0.06 12.84 0.179 12.96 ;
     RECT  0.084 12.96 0.179 12.984 ;
     RECT  0.06 12.984 0.179 13.104 ;
     RECT  0.084 13.104 0.179 13.128 ;
     RECT  0.06 13.128 0.179 13.2 ;
     RECT  0.084 13.2 0.179 13.224 ;
     RECT  0.06 13.224 0.179 13.344 ;
     RECT  0.084 13.344 0.179 13.368 ;
     RECT  0.06 13.368 0.179 13.488 ;
     RECT  0.084 13.488 0.179 13.512 ;
     RECT  0.06 13.512 0.179 13.632 ;
     RECT  0.084 13.632 0.179 13.656 ;
     RECT  0.06 13.656 0.179 13.776 ;
     RECT  0.084 13.776 0.179 13.8 ;
     RECT  0.06 13.8 0.179 13.872 ;
     RECT  0.084 13.872 0.179 13.896 ;
     RECT  0.06 13.896 0.179 14.016 ;
     RECT  0.084 14.016 0.179 14.04 ;
     RECT  0.06 14.04 0.179 14.16 ;
     RECT  0.084 14.16 0.179 14.184 ;
     RECT  0.06 14.184 0.179 14.304 ;
     RECT  0.084 14.304 0.179 14.328 ;
     RECT  0.06 14.328 0.179 14.448 ;
     RECT  0.084 14.448 0.179 14.472 ;
     RECT  0.06 14.472 0.179 14.544 ;
     RECT  0.084 14.544 0.179 14.568 ;
     RECT  0.06 14.568 0.179 14.688 ;
     RECT  0.084 14.688 0.179 14.712 ;
     RECT  0.06 14.712 0.179 14.832 ;
     RECT  0.084 14.832 0.179 14.856 ;
     RECT  0.06 14.856 0.179 14.976 ;
     RECT  0.084 14.976 0.179 15 ;
     RECT  0.06 15 0.179 15.12 ;
     RECT  0.084 15.12 0.179 15.144 ;
     RECT  0.06 15.144 0.179 15.216 ;
     RECT  0.084 15.216 0.179 15.24 ;
     RECT  0.06 15.24 0.179 15.36 ;
     RECT  0.084 15.36 0.179 15.384 ;
     RECT  0.06 15.384 0.179 15.504 ;
     RECT  0.084 15.504 0.179 15.528 ;
     RECT  0.06 15.528 0.179 15.648 ;
     RECT  0.084 15.648 0.179 15.672 ;
     RECT  0.06 15.672 0.179 15.792 ;
     RECT  0.084 15.792 0.179 15.816 ;
     RECT  0.06 15.816 0.179 15.888 ;
     RECT  0.084 15.888 0.179 15.912 ;
     RECT  0.06 15.912 0.179 16.032 ;
     RECT  0.084 16.032 0.179 16.056 ;
     RECT  0.06 16.056 0.179 16.176 ;
     RECT  0.084 16.176 0.179 16.2 ;
     RECT  0.06 16.2 0.179 16.32 ;
     RECT  0.084 16.32 0.179 16.344 ;
     RECT  0.06 16.344 0.179 16.464 ;
     RECT  0.084 16.464 0.179 16.488 ;
     RECT  0.06 16.488 0.179 16.56 ;
     RECT  0.084 16.56 0.179 16.584 ;
     RECT  0.06 16.584 0.179 16.704 ;
     RECT  0.084 16.704 0.179 16.728 ;
     RECT  0.06 16.728 0.179 16.848 ;
     RECT  0.084 16.848 0.179 16.872 ;
     RECT  0.06 16.872 0.179 16.992 ;
     RECT  0.084 16.992 0.179 17.016 ;
     RECT  0.06 17.016 0.179 17.136 ;
     RECT  0.084 17.136 0.179 17.16 ;
     RECT  0.06 17.16 0.179 17.232 ;
     RECT  0.084 17.232 0.179 17.256 ;
     RECT  0.06 17.256 0.179 17.376 ;
     RECT  0.084 17.376 0.179 17.4 ;
     RECT  0.06 17.4 0.179 17.52 ;
     RECT  0.084 17.52 0.179 17.544 ;
     RECT  0.06 17.544 0.179 17.664 ;
     RECT  0.084 17.664 0.179 17.688 ;
     RECT  0.06 17.688 0.179 17.808 ;
     RECT  0.084 17.808 0.179 17.832 ;
     RECT  0.06 17.832 0.179 17.904 ;
     RECT  0.084 17.904 0.179 17.928 ;
     RECT  0.06 17.928 0.179 18.048 ;
     RECT  0.084 18.048 0.179 18.072 ;
     RECT  0.06 18.072 0.179 18.192 ;
     RECT  0.084 18.192 0.179 18.216 ;
     RECT  0.06 18.216 0.179 18.336 ;
     RECT  0.084 18.336 0.179 18.36 ;
     RECT  0.06 18.36 0.179 18.48 ;
     RECT  0.084 18.48 0.179 18.504 ;
     RECT  0.06 18.504 0.179 18.576 ;
     RECT  0.084 18.576 0.179 18.6 ;
     RECT  0.06 18.6 0.179 18.72 ;
     RECT  0.084 18.72 0.179 18.744 ;
     RECT  0.06 18.744 0.179 18.864 ;
     RECT  0.084 18.864 0.179 18.888 ;
     RECT  0.06 18.888 0.179 19.008 ;
     RECT  0.084 19.008 0.179 19.032 ;
     RECT  0.06 19.032 0.179 19.152 ;
     RECT  0.084 19.152 0.179 19.176 ;
     RECT  0.06 19.176 0.179 19.248 ;
     RECT  0.084 19.248 0.179 19.272 ;
     RECT  0.06 19.272 0.179 19.392 ;
     RECT  0.084 19.392 0.179 19.416 ;
     RECT  0.06 19.416 0.179 19.536 ;
     RECT  0.084 19.536 0.179 19.56 ;
     RECT  0.06 19.56 0.179 19.68 ;
     RECT  0.084 19.68 0.179 19.704 ;
     RECT  0.06 19.704 0.179 19.824 ;
     RECT  0.084 19.824 0.179 19.848 ;
     RECT  0.06 19.848 0.179 19.92 ;
     RECT  0.084 19.92 0.179 19.944 ;
     RECT  0.06 19.944 0.179 20.064 ;
     RECT  0.084 20.064 0.179 20.088 ;
     RECT  0.06 20.088 0.179 20.208 ;
     RECT  0.084 20.208 0.179 20.232 ;
     RECT  0.06 20.232 0.179 20.352 ;
     RECT  0.084 20.352 0.179 20.376 ;
     RECT  0.06 20.376 0.179 20.496 ;
     RECT  0.084 20.496 0.179 20.52 ;
     RECT  0.06 20.52 0.179 20.592 ;
     RECT  0.084 20.592 0.179 20.616 ;
     RECT  0.06 20.616 0.179 20.736 ;
     RECT  0.084 20.736 0.179 20.76 ;
     RECT  0.06 20.76 0.179 20.88 ;
     RECT  0.084 20.88 0.179 20.904 ;
     RECT  0.06 20.904 0.179 21.024 ;
     RECT  0.084 21.024 0.179 21.048 ;
     RECT  0.06 21.048 0.179 21.168 ;
     RECT  0.084 21.168 0.179 21.192 ;
     RECT  0.06 21.192 0.179 21.264 ;
     RECT  0.084 21.264 0.179 21.288 ;
     RECT  0.06 21.288 0.179 21.408 ;
     RECT  0.084 21.408 0.179 21.432 ;
     RECT  0.06 21.432 0.179 21.552 ;
     RECT  0.084 21.552 0.179 21.576 ;
     RECT  0.06 21.576 0.179 21.696 ;
     RECT  0.084 21.696 0.179 21.72 ;
     RECT  0.06 21.72 0.179 21.84 ;
     RECT  0.084 21.84 0.179 21.864 ;
     RECT  0.06 21.864 0.179 21.936 ;
     RECT  0.084 21.936 0.179 21.96 ;
     RECT  0.06 21.96 0.179 22.08 ;
     RECT  0.084 22.08 0.179 22.104 ;
     RECT  0.06 22.104 0.179 22.224 ;
     RECT  0.084 22.224 0.179 22.248 ;
     RECT  0.06 22.248 0.179 22.368 ;
     RECT  0.084 22.368 0.179 22.392 ;
     RECT  0.06 22.392 0.179 22.512 ;
     RECT  0.084 22.512 0.179 22.536 ;
     RECT  0.06 22.536 0.179 22.608 ;
     RECT  0.084 22.608 0.179 22.632 ;
     RECT  0.06 22.632 0.179 22.752 ;
     RECT  0.084 22.752 0.179 22.776 ;
     RECT  0.06 22.776 0.179 22.896 ;
     RECT  0.084 22.896 0.179 22.92 ;
     RECT  0.06 22.92 0.179 23.04 ;
     RECT  0.084 23.04 0.179 23.064 ;
     RECT  0.06 23.064 0.179 23.184 ;
     RECT  0.084 23.184 0.179 23.208 ;
     RECT  0.06 23.208 0.179 23.28 ;
     RECT  0.084 23.28 0.179 23.304 ;
     RECT  0.06 23.304 0.179 23.424 ;
     RECT  0.084 23.424 0.179 23.448 ;
     RECT  0.06 23.448 0.179 23.568 ;
     RECT  0.084 23.568 0.179 23.592 ;
     RECT  0.06 23.592 0.179 23.712 ;
     RECT  0.084 23.712 0.179 23.736 ;
     RECT  0.06 23.736 0.179 23.856 ;
     RECT  0.084 23.856 0.179 23.88 ;
     RECT  0.06 23.88 0.179 23.952 ;
     RECT  0.084 23.952 0.179 23.976 ;
     RECT  0.06 23.976 0.179 24.096 ;
     RECT  0.084 24.096 0.179 24.12 ;
     RECT  0.06 24.12 0.179 24.24 ;
     RECT  0.084 24.24 0.179 24.264 ;
     RECT  0.06 24.264 0.179 24.384 ;
     RECT  0.084 24.384 0.179 24.408 ;
     RECT  0.06 24.408 0.179 24.528 ;
     RECT  0.084 24.528 0.179 24.552 ;
     RECT  0.06 24.552 0.179 24.624 ;
     RECT  0.084 24.624 0.179 24.648 ;
     RECT  0.06 24.648 0.179 24.768 ;
     RECT  0.084 24.768 0.179 24.792 ;
     RECT  0.06 24.792 0.179 24.912 ;
     RECT  0.084 24.912 0.179 24.936 ;
     RECT  0.06 24.936 0.179 25.056 ;
     RECT  0.084 25.056 0.179 25.08 ;
     RECT  0.06 25.08 0.179 25.2 ;
     RECT  0.084 25.2 0.179 25.224 ;
     RECT  0.06 25.224 0.179 25.296 ;
     RECT  0.084 25.296 0.179 25.32 ;
     RECT  0.06 25.32 0.179 25.44 ;
     RECT  0.084 25.44 0.179 25.464 ;
     RECT  0.06 25.464 0.179 25.584 ;
     RECT  0.084 25.584 0.179 25.608 ;
     RECT  0.06 25.608 0.179 25.728 ;
     RECT  0.084 25.728 0.179 25.752 ;
     RECT  0.06 25.752 0.179 25.872 ;
     RECT  0.084 25.872 0.179 25.896 ;
     RECT  0.06 25.896 0.179 25.968 ;
     RECT  0.084 25.968 0.179 25.992 ;
     RECT  0.06 25.992 0.179 26.112 ;
     RECT  0.084 26.112 0.179 26.136 ;
     RECT  0.06 26.136 0.179 26.256 ;
     RECT  0.084 26.256 0.179 26.28 ;
     RECT  0.06 26.28 0.179 26.4 ;
     RECT  0.084 26.4 0.179 26.424 ;
     RECT  0.06 26.424 0.179 26.544 ;
     RECT  0.084 26.544 0.179 26.568 ;
     RECT  0.06 26.568 0.179 26.64 ;
     RECT  0.084 26.64 0.179 26.664 ;
     RECT  0.06 26.664 0.179 27.072 ;
     RECT  0.084 27.072 0.179 27.096 ;
     RECT  0.06 27.096 0.179 27.456 ;
     RECT  0.084 27.456 0.179 27.48 ;
     RECT  0.06 27.48 0.179 27.6 ;
     RECT  0.084 27.6 0.179 27.624 ;
     RECT  0.06 27.624 0.179 27.744 ;
     RECT  0.084 27.744 0.179 27.768 ;
     RECT  0.06 27.768 0.179 27.888 ;
     RECT  0.084 27.888 0.179 27.912 ;
     RECT  0.06 27.912 0.179 27.984 ;
     RECT  0.084 27.984 0.179 28.008 ;
     RECT  0.06 28.008 0.179 28.128 ;
     RECT  0.084 28.128 0.179 28.152 ;
     RECT  0.06 28.152 0.179 28.272 ;
     RECT  0.084 28.272 0.179 28.296 ;
     RECT  0.06 28.296 0.179 28.416 ;
     RECT  0.084 28.416 0.179 28.44 ;
     RECT  0.06 28.44 0.179 28.56 ;
     RECT  0.084 28.56 0.179 28.584 ;
     RECT  0.06 28.584 0.179 28.656 ;
     RECT  0.084 28.656 0.179 28.68 ;
     RECT  0.06 28.68 0.179 28.8 ;
     RECT  0.084 28.8 0.179 28.824 ;
     RECT  0.06 28.824 0.179 28.944 ;
     RECT  0.084 28.944 0.179 28.968 ;
     RECT  0.06 28.968 0.179 29.088 ;
     RECT  0.084 29.088 0.179 29.112 ;
     RECT  0.06 29.112 0.179 29.232 ;
     RECT  0.084 29.232 0.179 29.256 ;
     RECT  0.06 29.256 0.179 29.328 ;
     RECT  0.084 29.328 0.179 29.352 ;
     RECT  0.06 29.352 0.179 29.472 ;
     RECT  0.084 29.472 0.179 29.496 ;
     RECT  0.06 29.496 0.179 29.616 ;
     RECT  0.084 29.616 0.179 29.64 ;
     RECT  0.06 29.64 0.179 29.76 ;
     RECT  0.084 29.76 0.179 29.784 ;
     RECT  0.06 29.784 0.179 29.904 ;
     RECT  0.084 29.904 0.179 29.928 ;
     RECT  0.06 29.928 0.179 30 ;
     RECT  0.084 30 0.179 30.024 ;
     RECT  0.06 30.024 0.179 30.144 ;
     RECT  0.084 30.144 0.179 30.168 ;
     RECT  0.06 30.168 0.179 30.288 ;
     RECT  0.084 30.288 0.179 30.312 ;
     RECT  0.06 30.312 0.179 30.432 ;
     RECT  0.084 30.432 0.179 30.456 ;
     RECT  0.06 30.456 0.179 30.576 ;
     RECT  0.084 30.576 0.179 30.6 ;
     RECT  0.06 30.6 0.179 30.672 ;
     RECT  0.084 30.672 0.179 30.696 ;
     RECT  0.06 30.696 0.179 30.816 ;
     RECT  0.084 30.816 0.179 30.84 ;
     RECT  0.06 30.84 0.179 30.96 ;
     RECT  0.084 30.96 0.179 30.984 ;
     RECT  0.06 30.984 0.179 31.104 ;
     RECT  0.084 31.104 0.179 31.128 ;
     RECT  0.06 31.128 0.179 31.248 ;
     RECT  0.084 31.248 0.179 31.272 ;
     RECT  0.06 31.272 0.179 31.344 ;
     RECT  0.084 31.344 0.179 31.368 ;
     RECT  0.06 31.368 0.179 31.488 ;
     RECT  0.084 31.488 0.179 31.512 ;
     RECT  0.06 31.512 0.179 31.632 ;
     RECT  0.084 31.632 0.179 31.656 ;
     RECT  0.06 31.656 0.179 31.776 ;
     RECT  0.084 31.776 0.179 31.8 ;
     RECT  0.06 31.8 0.179 31.92 ;
     RECT  0.084 31.92 0.179 31.944 ;
     RECT  0.06 31.944 0.179 32.016 ;
     RECT  0.084 32.016 0.179 32.04 ;
     RECT  0.06 32.04 0.179 32.16 ;
     RECT  0.084 32.16 0.179 32.184 ;
     RECT  0.06 32.184 0.179 32.304 ;
     RECT  0.084 32.304 0.179 32.328 ;
     RECT  0.06 32.328 0.179 32.448 ;
     RECT  0.084 32.448 0.179 32.472 ;
     RECT  0.06 32.472 0.179 32.592 ;
     RECT  0.084 32.592 0.179 32.616 ;
     RECT  0.06 32.616 0.179 32.688 ;
     RECT  0.084 32.688 0.179 32.712 ;
     RECT  0.06 32.712 0.179 32.832 ;
     RECT  0.084 32.832 0.179 32.856 ;
     RECT  0.06 32.856 0.179 32.976 ;
     RECT  0.084 32.976 0.179 33 ;
     RECT  0.06 33 0.179 33.12 ;
     RECT  0.084 33.12 0.179 33.144 ;
     RECT  0.06 33.144 0.179 33.264 ;
     RECT  0.084 33.264 0.179 33.288 ;
     RECT  0.06 33.288 0.179 33.36 ;
     RECT  0.084 33.36 0.179 33.384 ;
     RECT  0.06 33.384 0.179 33.504 ;
     RECT  0.084 33.504 0.179 33.528 ;
     RECT  0.06 33.528 0.179 33.648 ;
     RECT  0.084 33.648 0.179 33.672 ;
     RECT  0.06 33.672 0.179 33.792 ;
     RECT  0.084 33.792 0.179 33.816 ;
     RECT  0.06 33.816 0.179 33.936 ;
     RECT  0.084 33.936 0.179 33.96 ;
     RECT  0.06 33.96 0.179 34.032 ;
     RECT  0.084 34.032 0.179 34.056 ;
     RECT  0.06 34.056 0.179 34.176 ;
     RECT  0.084 34.176 0.179 34.2 ;
     RECT  0.06 34.2 0.179 34.32 ;
     RECT  0.084 34.32 0.179 34.344 ;
     RECT  0.06 34.344 0.179 34.464 ;
     RECT  0.084 34.464 0.179 34.488 ;
     RECT  0.06 34.488 0.179 34.608 ;
     RECT  0.084 34.608 0.179 34.632 ;
     RECT  0.06 34.632 0.179 34.704 ;
     RECT  0.084 34.704 0.179 34.728 ;
     RECT  0.06 34.728 0.179 34.848 ;
     RECT  0.084 34.848 0.179 34.872 ;
     RECT  0.06 34.872 0.179 34.992 ;
     RECT  0.084 34.992 0.179 35.016 ;
     RECT  0.06 35.016 0.179 35.136 ;
     RECT  0.084 35.136 0.179 35.16 ;
     RECT  0.06 35.16 0.179 35.28 ;
     RECT  0.084 35.28 0.179 35.304 ;
     RECT  0.06 35.304 0.179 35.376 ;
     RECT  0.084 35.376 0.179 35.4 ;
     RECT  0.06 35.4 0.179 35.52 ;
     RECT  0.084 35.52 0.179 35.544 ;
     RECT  0.06 35.544 0.179 35.664 ;
     RECT  0.084 35.664 0.179 35.688 ;
     RECT  0.06 35.688 0.179 35.808 ;
     RECT  0.084 35.808 0.179 35.832 ;
     RECT  0.06 35.832 0.179 35.952 ;
     RECT  0.084 35.952 0.179 35.976 ;
     RECT  0.06 35.976 0.179 36.048 ;
     RECT  0.084 36.048 0.179 36.072 ;
     RECT  0.06 36.072 0.179 36.192 ;
     RECT  0.084 36.192 0.179 36.216 ;
     RECT  0.06 36.216 0.179 36.336 ;
     RECT  0.084 36.336 0.179 36.36 ;
     RECT  0.06 36.36 0.179 36.48 ;
     RECT  0.084 36.48 0.179 36.504 ;
     RECT  0.06 36.504 0.179 36.624 ;
     RECT  0.084 36.624 0.179 36.648 ;
     RECT  0.06 36.648 0.179 36.72 ;
     RECT  0.084 36.72 0.179 36.744 ;
     RECT  0.06 36.744 0.179 36.864 ;
     RECT  0.084 36.864 0.179 36.888 ;
     RECT  0.06 36.888 0.179 37.008 ;
     RECT  0.084 37.008 0.179 37.032 ;
     RECT  0.06 37.032 0.179 37.152 ;
     RECT  0.084 37.152 0.179 37.176 ;
     RECT  0.06 37.176 0.179 37.296 ;
     RECT  0.084 37.296 0.179 37.32 ;
     RECT  0.06 37.32 0.179 37.392 ;
     RECT  0.084 37.392 0.179 37.416 ;
     RECT  0.06 37.416 0.179 37.536 ;
     RECT  0.084 37.536 0.179 37.56 ;
     RECT  0.06 37.56 0.179 37.68 ;
     RECT  0.084 37.68 0.179 37.704 ;
     RECT  0.06 37.704 0.179 37.824 ;
     RECT  0.084 37.824 0.179 37.848 ;
     RECT  0.06 37.848 0.179 37.968 ;
     RECT  0.084 37.968 0.179 37.992 ;
     RECT  0.06 37.992 0.179 38.064 ;
     RECT  0.084 38.064 0.179 38.088 ;
     RECT  0.06 38.088 0.179 38.208 ;
     RECT  0.084 38.208 0.179 38.232 ;
     RECT  0.06 38.232 0.179 38.352 ;
     RECT  0.084 38.352 0.179 38.376 ;
     RECT  0.06 38.376 0.179 38.496 ;
     RECT  0.084 38.496 0.179 38.52 ;
     RECT  0.06 38.52 0.179 38.64 ;
     RECT  0.084 38.64 0.179 38.664 ;
     RECT  0.06 38.664 0.179 38.736 ;
     RECT  0.084 38.736 0.179 38.76 ;
     RECT  0.06 38.76 0.179 38.88 ;
     RECT  0.084 38.88 0.179 38.904 ;
     RECT  0.06 38.904 0.179 39.024 ;
     RECT  0.084 39.024 0.179 39.048 ;
     RECT  0.06 39.048 0.179 39.168 ;
     RECT  0.084 39.168 0.179 39.192 ;
     RECT  0.06 39.192 0.179 39.312 ;
     RECT  0.084 39.312 0.179 39.336 ;
     RECT  0.06 39.336 0.179 39.408 ;
     RECT  0.084 39.408 0.179 39.432 ;
     RECT  0.06 39.432 0.179 39.552 ;
     RECT  0.084 39.552 0.179 39.576 ;
     RECT  0.06 39.576 0.179 39.696 ;
     RECT  0.084 39.696 0.179 39.72 ;
     RECT  0.06 39.72 0.179 39.84 ;
     RECT  0.084 39.84 0.179 39.864 ;
     RECT  0.06 39.864 0.179 39.984 ;
     RECT  0.084 39.984 0.179 40.008 ;
     RECT  0.06 40.008 0.179 40.08 ;
     RECT  0.084 40.08 0.179 40.104 ;
     RECT  0.06 40.104 0.179 40.224 ;
     RECT  0.084 40.224 0.179 40.248 ;
     RECT  0.06 40.248 0.179 40.368 ;
     RECT  0.084 40.368 0.179 40.392 ;
     RECT  0.06 40.392 0.179 40.512 ;
     RECT  0.084 40.512 0.179 40.536 ;
     RECT  0.06 40.536 0.179 40.656 ;
     RECT  0.084 40.656 0.179 40.68 ;
     RECT  0.06 40.68 0.179 40.752 ;
     RECT  0.084 40.752 0.179 40.776 ;
     RECT  0.06 40.776 0.179 40.896 ;
     RECT  0.084 40.896 0.179 40.92 ;
     RECT  0.06 40.92 0.179 41.04 ;
     RECT  0.084 41.04 0.179 41.064 ;
     RECT  0.06 41.064 0.179 41.184 ;
     RECT  0.084 41.184 0.179 41.208 ;
     RECT  0.06 41.208 0.179 41.328 ;
     RECT  0.084 41.328 0.179 41.352 ;
     RECT  0.06 41.352 0.179 41.424 ;
     RECT  0.084 41.424 0.179 41.448 ;
     RECT  0.06 41.448 0.179 41.568 ;
     RECT  0.084 41.568 0.179 41.592 ;
     RECT  0.06 41.592 0.179 41.712 ;
     RECT  0.084 41.712 0.179 41.736 ;
     RECT  0.06 41.736 0.179 41.856 ;
     RECT  0.084 41.856 0.179 41.88 ;
     RECT  0.06 41.88 0.179 42 ;
     RECT  0.084 42 0.179 42.024 ;
     RECT  0.06 42.024 0.179 42.096 ;
     RECT  0.084 42.096 0.179 42.12 ;
     RECT  0.06 42.12 0.179 42.24 ;
     RECT  0.084 42.24 0.179 42.264 ;
     RECT  0.06 42.264 0.179 42.384 ;
     RECT  0.084 42.384 0.179 42.408 ;
     RECT  0.06 42.408 0.179 42.528 ;
     RECT  0.084 42.528 0.179 42.552 ;
     RECT  0.06 42.552 0.179 42.672 ;
     RECT  0.084 42.672 0.179 42.696 ;
     RECT  0.06 42.696 0.179 42.768 ;
     RECT  0.084 42.768 0.179 42.792 ;
     RECT  0.06 42.792 0.179 42.912 ;
     RECT  0.084 42.912 0.179 42.936 ;
     RECT  0.06 42.936 0.179 43.056 ;
     RECT  0.084 43.056 0.179 43.08 ;
     RECT  0.06 43.08 0.179 43.2 ;
     RECT  0.084 43.2 0.179 43.224 ;
     RECT  0.06 43.224 0.179 43.344 ;
     RECT  0.084 43.344 0.179 43.368 ;
     RECT  0.06 43.368 0.179 43.44 ;
     RECT  0.084 43.44 0.179 43.464 ;
     RECT  0.06 43.464 0.179 43.584 ;
     RECT  0.084 43.584 0.179 43.608 ;
     RECT  0.06 43.608 0.179 43.728 ;
     RECT  0.084 43.728 0.179 43.752 ;
     RECT  0.06 43.752 0.179 43.872 ;
     RECT  0.084 43.872 0.179 43.896 ;
     RECT  0.06 43.896 0.179 44.016 ;
     RECT  0.084 44.016 0.179 44.04 ;
     RECT  0.06 44.04 0.179 44.112 ;
     RECT  0.084 44.112 0.179 44.136 ;
     RECT  0.06 44.136 0.179 44.256 ;
     RECT  0.084 44.256 0.179 44.28 ;
     RECT  0.06 44.28 0.179 44.4 ;
     RECT  0.084 44.4 0.179 44.424 ;
     RECT  0.06 44.424 0.179 44.544 ;
     RECT  0.084 44.544 0.179 44.568 ;
     RECT  0.06 44.568 0.179 44.688 ;
     RECT  0.084 44.688 0.179 44.712 ;
     RECT  0.06 44.712 0.179 44.784 ;
     RECT  0.084 44.784 0.179 44.808 ;
     RECT  0.06 44.808 0.179 44.928 ;
     RECT  0.084 44.928 0.179 44.952 ;
     RECT  0.06 44.952 0.179 45.072 ;
     RECT  0.084 45.072 0.179 45.096 ;
     RECT  0.06 45.096 0.179 45.216 ;
     RECT  0.084 45.216 0.179 45.24 ;
     RECT  0.06 45.24 0.179 45.36 ;
     RECT  0.084 45.36 0.179 45.384 ;
     RECT  0.06 45.384 0.179 45.456 ;
     RECT  0.084 45.456 0.179 45.48 ;
     RECT  0.06 45.48 0.179 45.6 ;
     RECT  0.084 45.6 0.179 45.624 ;
     RECT  0.06 45.624 0.179 45.744 ;
     RECT  0.084 45.744 0.179 45.768 ;
     RECT  0.06 45.768 0.179 45.888 ;
     RECT  0.084 45.888 0.179 45.912 ;
     RECT  0.06 45.912 0.179 46.032 ;
     RECT  0.084 46.032 0.179 46.056 ;
     RECT  0.06 46.056 0.179 46.128 ;
     RECT  0.084 46.128 0.179 46.152 ;
     RECT  0.06 46.152 0.179 46.272 ;
     RECT  0.084 46.272 0.179 46.296 ;
     RECT  0.06 46.296 0.179 46.416 ;
     RECT  0.084 46.416 0.179 46.44 ;
     RECT  0.06 46.44 0.179 46.56 ;
     RECT  0.084 46.56 0.179 46.584 ;
     RECT  0.06 46.584 0.179 46.704 ;
     RECT  0.084 46.704 0.179 46.728 ;
     RECT  0.06 46.728 0.179 46.8 ;
     RECT  0.084 46.8 0.179 46.824 ;
     RECT  0.06 46.824 0.179 46.944 ;
     RECT  0.084 46.944 0.179 46.968 ;
     RECT  0.06 46.968 0.179 47.088 ;
     RECT  0.084 47.088 0.179 47.112 ;
     RECT  0.06 47.112 0.179 47.232 ;
     RECT  0.084 47.232 0.179 47.256 ;
     RECT  0.06 47.256 0.179 47.376 ;
     RECT  0.084 47.376 0.179 47.4 ;
     RECT  0.06 47.4 0.179 47.472 ;
     RECT  0.084 47.472 0.179 47.496 ;
     RECT  0.06 47.496 0.179 47.616 ;
     RECT  0.084 47.616 0.179 47.64 ;
     RECT  0.06 47.64 0.179 47.76 ;
     RECT  0.084 47.76 0.179 47.784 ;
     RECT  0.06 47.784 0.179 47.904 ;
     RECT  0.084 47.904 0.179 47.928 ;
     RECT  0.06 47.928 0.179 48.048 ;
     RECT  0.084 48.048 0.179 48.072 ;
     RECT  0.06 48.072 0.179 48.144 ;
     RECT  0.084 48.144 0.179 48.168 ;
     RECT  0.06 48.168 0.179 48.288 ;
     RECT  0.084 48.288 0.179 48.312 ;
     RECT  0.06 48.312 0.179 48.432 ;
     RECT  0.084 48.432 0.179 48.456 ;
     RECT  0.06 48.456 0.179 48.576 ;
     RECT  0.084 48.576 0.179 48.6 ;
     RECT  0.06 48.6 0.179 48.72 ;
     RECT  0.084 48.72 0.179 48.744 ;
     RECT  0.06 48.744 0.179 48.816 ;
     RECT  0.084 48.816 0.179 48.84 ;
     RECT  0.06 48.84 0.179 48.96 ;
     RECT  0.084 48.96 0.179 48.984 ;
     RECT  0.06 48.984 0.179 49.104 ;
     RECT  0.084 49.104 0.179 49.128 ;
     RECT  0.06 49.128 0.179 49.248 ;
     RECT  0.084 49.248 0.179 49.272 ;
     RECT  0.179 1.008 1.573 49.128 ;
     RECT  1.429 50.16 1.573 50.184 ;
     RECT  1.573 1.008 1.757 50.184 ;
     RECT  1.757 1.104 1.793 50.184 ;
     RECT  2.437 51.648 2.581 51.672 ;
     RECT  1.793 1.248 2.585 50.184 ;
     RECT  2.581 51.6 2.717 51.672 ;
     RECT  2.717 51.6 2.732 51.72 ;
     RECT  2.585 1.248 2.765 49.56 ;
     RECT  2.732 51.552 2.801 51.72 ;
     RECT  2.801 51.552 2.861 51.672 ;
     RECT  2.861 50.688 2.945 51.672 ;
     RECT  2.765 1.92 3.629 49.56 ;
     RECT  2.945 51.6 3.827 51.672 ;
     RECT  3.629 2.016 4.421 49.56 ;
     RECT  4.421 2.064 4.849 49.56 ;
     RECT  4.849 2.064 5.507 49.848 ;
     RECT  5.507 2.064 5.537 49.8 ;
     RECT  3.827 51.648 5.699 51.672 ;
     RECT  5.537 2.064 5.789 49.608 ;
     RECT  5.789 2.208 5.987 49.608 ;
     RECT  5.987 2.304 7.009 49.608 ;
     RECT  7.009 2.208 7.045 49.608 ;
     RECT  7.045 2.208 7.337 50.184 ;
     RECT  7.525 51.648 7.669 51.672 ;
     RECT  7.337 2.208 7.808 49.8 ;
     RECT  7.669 51.6 7.811 51.672 ;
     RECT  7.808 2.148 8.104 49.8 ;
     RECT  8.104 2.832 8.165 49.8 ;
     RECT  7.811 51.6 8.197 51.624 ;
     RECT  8.197 51.504 8.387 51.624 ;
     RECT  8.387 51.6 8.483 51.624 ;
     RECT  8.165 2.88 8.597 2.904 ;
     RECT  8.629 1.728 8.849 1.752 ;
     RECT  8.165 4.224 8.909 49.8 ;
     RECT  8.909 4.224 8.993 50.136 ;
     RECT  8.993 4.224 9.029 49.8 ;
     RECT  9.029 4.224 9.389 49.56 ;
     RECT  9.389 17.088 9.395 49.56 ;
     RECT  9.389 4.224 9.425 16.104 ;
     RECT  9.425 4.224 9.443 6.744 ;
     RECT  9.443 4.224 10.508 6.264 ;
     RECT  9.425 7.776 10.508 16.104 ;
     RECT  9.395 17.088 10.508 29.064 ;
     RECT  9.395 30.048 10.508 49.56 ;
     RECT  10.508 2.148 10.612 49.692 ;
     RECT  10.612 2.418 10.804 49.464 ;
     RECT  10.804 3.936 10.931 6.552 ;
     RECT  10.804 11.808 10.979 14.568 ;
     RECT  10.804 20.064 11.075 23.784 ;
     RECT  10.979 11.808 11.171 12.888 ;
     RECT  10.804 17.616 11.219 18.024 ;
     RECT  11.075 20.064 11.219 23.352 ;
     RECT  10.804 24.864 11.225 26.04 ;
     RECT  10.804 28.368 11.225 49.464 ;
     RECT  10.804 8.304 11.267 10.728 ;
     RECT  11.225 28.512 11.267 49.464 ;
     RECT  11.219 17.616 11.315 17.64 ;
     RECT  10.804 16.56 11.333 16.584 ;
     RECT  11.267 29.088 11.333 49.464 ;
     RECT  11.171 11.808 11.363 12.552 ;
     RECT  11.219 20.064 11.411 22.872 ;
     RECT  11.333 29.328 11.459 49.464 ;
     RECT  10.931 3.936 11.507 5.496 ;
     RECT  11.459 29.328 11.513 33 ;
     RECT  11.507 4.992 11.555 5.496 ;
     RECT  11.225 25.104 11.621 26.04 ;
     RECT  10.979 13.92 11.795 14.568 ;
     RECT  11.363 11.808 11.843 12.504 ;
     RECT  11.621 25.104 11.891 25.272 ;
     RECT  10.804 27.12 11.891 27.336 ;
     RECT  11.411 20.064 11.987 21.096 ;
     RECT  11.411 22.848 11.987 22.872 ;
     RECT  11.891 25.104 11.987 25.128 ;
     RECT  11.513 30.624 11.987 33 ;
     RECT  11.507 3.936 12.089 3.96 ;
     RECT  11.891 27.312 12.229 27.336 ;
     RECT  11.459 34.176 12.233 49.464 ;
     RECT  11.267 10.128 12.265 10.728 ;
     RECT  11.513 29.328 12.589 29.4 ;
     RECT  11.987 31.68 12.589 33 ;
     RECT  12.445 34.08 12.589 34.104 ;
     RECT  11.987 30.624 12.985 30.648 ;
     RECT  12.229 27.312 13.093 27.912 ;
     RECT  12.589 29.328 13.093 29.64 ;
     RECT  12.985 30.624 13.093 30.696 ;
     RECT  11.555 4.992 13.208 5.016 ;
     RECT  10.931 6.528 13.208 6.552 ;
     RECT  11.267 8.304 13.208 8.856 ;
     RECT  12.265 10.128 13.208 10.824 ;
     RECT  11.843 11.808 13.208 12.072 ;
     RECT  11.795 13.92 13.208 13.944 ;
     RECT  11.987 20.064 13.208 20.712 ;
     RECT  13.093 27.312 13.208 30.696 ;
     RECT  12.589 31.68 13.208 34.104 ;
     RECT  12.233 35.184 13.208 49.464 ;
     RECT  13.208 2.148 13.312 49.692 ;
     RECT  13.312 2.418 13.504 49.422 ;
     RECT  13.504 45.168 13.529 45.192 ;
     RECT  13.504 3.84 13.619 3.864 ;
     RECT  13.504 9.792 13.619 10.248 ;
     RECT  13.504 15.984 13.619 16.008 ;
     RECT  13.504 34.896 13.619 35.448 ;
     RECT  13.504 36.624 13.673 37.656 ;
     RECT  13.504 48.768 13.673 49.032 ;
     RECT  13.673 37.632 13.709 37.656 ;
     RECT  13.504 39.312 13.709 40.968 ;
     RECT  13.504 42.192 13.709 43.32 ;
     RECT  13.673 36.624 13.745 36.648 ;
     RECT  13.709 42.576 13.745 43.08 ;
     RECT  13.504 4.992 13.763 5.016 ;
     RECT  13.504 46.848 13.763 46.872 ;
     RECT  13.673 48.768 13.853 48.792 ;
     RECT  13.504 11.952 13.925 11.976 ;
     RECT  13.709 39.312 13.925 40.68 ;
     RECT  13.925 40.272 13.997 40.68 ;
     RECT  13.745 42.576 14.177 42.792 ;
     RECT  13.619 10.176 14.213 10.2 ;
     RECT  14.177 42.576 14.321 42.6 ;
     RECT  13.997 40.272 14.501 40.296 ;
    LAYER M5 ;
     RECT  0.144 1.525 0.168 1.669 ;
     RECT  0.144 1.669 0.216 2.051 ;
     RECT  2.4 2.137 2.52 2.151 ;
     RECT  5.1 2.137 5.22 2.151 ;
     RECT  10.5 2.137 10.62 2.151 ;
     RECT  13.2 2.137 13.32 2.151 ;
     RECT  2.4 2.151 2.712 2.197 ;
     RECT  5.1 2.151 5.412 2.197 ;
     RECT  7.8 2.137 8.112 2.197 ;
     RECT  5.1 2.197 5.976 2.245 ;
     RECT  2.4 2.197 3.432 2.485 ;
     RECT  4.464 2.245 5.976 2.485 ;
     RECT  2.4 2.485 5.976 2.773 ;
     RECT  7.248 2.197 8.112 2.773 ;
     RECT  0.144 2.051 0.168 3.107 ;
     RECT  13.2 2.151 13.512 3.829 ;
     RECT  10.5 2.151 10.812 3.925 ;
     RECT  10.5 3.925 10.92 4.213 ;
     RECT  13.2 3.829 13.608 4.981 ;
     RECT  2.4 2.773 8.112 5.461 ;
     RECT  9.12 5.029 9.144 5.461 ;
     RECT  10.5 4.213 11.496 5.461 ;
     RECT  2.4 5.461 9.144 5.845 ;
     RECT  10.5 5.461 11.544 6.517 ;
     RECT  13.2 4.981 13.752 6.517 ;
     RECT  2.4 5.845 9.192 6.709 ;
     RECT  2.4 6.709 9.432 7.765 ;
     RECT  10.5 6.517 13.752 7.765 ;
     RECT  2.4 7.765 13.752 7.909 ;
     RECT  0.144 7.333 0.168 8.485 ;
     RECT  0.144 8.485 0.312 9.107 ;
     RECT  0.144 9.107 0.216 10.597 ;
     RECT  0.144 10.597 0.264 11.651 ;
     RECT  0.192 11.651 0.264 12.277 ;
     RECT  2.304 7.909 13.752 12.371 ;
     RECT  0.192 12.277 0.36 12.611 ;
     RECT  0.192 12.611 0.312 13.189 ;
     RECT  0.144 13.189 0.312 14.197 ;
     RECT  2.4 12.371 13.752 14.437 ;
     RECT  0.144 14.197 0.36 14.579 ;
     RECT  0.144 14.579 0.264 14.915 ;
     RECT  0.24 14.915 0.264 15.781 ;
     RECT  0.24 15.781 0.312 15.877 ;
     RECT  0.24 15.877 0.36 15.925 ;
     RECT  0.192 15.925 0.36 16.019 ;
     RECT  0.192 16.019 0.312 16.549 ;
     RECT  0.144 16.549 0.312 18.611 ;
     RECT  0.144 18.611 0.168 19.813 ;
     RECT  0.144 19.813 0.312 20.579 ;
     RECT  0.144 20.579 0.216 21.779 ;
     RECT  0.192 21.779 0.216 22.021 ;
     RECT  0.192 22.021 0.552 22.403 ;
     RECT  0.192 22.403 0.408 22.885 ;
     RECT  0.144 22.885 0.408 24.373 ;
     RECT  0.144 24.373 0.456 24.517 ;
     RECT  2.256 14.437 13.752 24.661 ;
     RECT  2.208 24.661 13.752 25.043 ;
     RECT  0.144 24.517 0.504 25.141 ;
     RECT  0.144 25.141 1.176 25.331 ;
     RECT  0.144 25.331 0.408 25.715 ;
     RECT  0.192 25.715 0.408 26.629 ;
     RECT  0.192 26.629 0.552 26.819 ;
     RECT  0.288 26.819 0.552 26.867 ;
     RECT  0.528 26.867 0.552 27.107 ;
     RECT  2.256 25.043 13.752 28.165 ;
     RECT  0.192 28.165 0.216 28.405 ;
     RECT  0.144 28.405 0.216 28.453 ;
     RECT  0.144 28.453 0.264 28.691 ;
     RECT  0.144 28.691 0.216 29.315 ;
     RECT  0.288 29.749 0.312 30.805 ;
     RECT  0.288 30.805 0.36 31.093 ;
     RECT  2.208 28.165 13.752 31.957 ;
     RECT  2.16 31.957 13.752 32.483 ;
     RECT  0.144 31.093 0.36 33.541 ;
     RECT  0.144 33.541 0.408 34.117 ;
     RECT  0.144 34.117 0.504 35.939 ;
     RECT  0.192 35.939 0.504 35.989 ;
     RECT  0.192 35.989 1.176 36.275 ;
     RECT  0.192 36.275 0.312 37.859 ;
     RECT  0.192 37.859 0.216 38.387 ;
     RECT  0.144 38.725 0.168 40.405 ;
     RECT  0.144 40.405 0.216 42.275 ;
     RECT  0.192 42.275 0.216 42.707 ;
     RECT  2.208 32.483 13.752 42.709 ;
     RECT  0.432 43.333 0.456 43.765 ;
     RECT  0.24 43.765 0.456 43.813 ;
     RECT  0.144 43.813 0.456 44.341 ;
     RECT  0.144 44.341 0.504 44.725 ;
     RECT  0.144 44.725 1.176 46.069 ;
     RECT  2.16 42.709 13.752 46.069 ;
     RECT  0.144 46.069 13.752 46.211 ;
     RECT  13.2 46.211 13.752 46.883 ;
     RECT  0.144 46.211 11.784 47.269 ;
     RECT  13.2 46.883 13.512 47.269 ;
     RECT  0.144 47.269 13.512 49.043 ;
     RECT  0.144 49.043 11.4 49.139 ;
     RECT  0.144 49.139 10.812 49.283 ;
     RECT  1.008 49.283 10.812 49.571 ;
     RECT  10.5 49.571 10.812 49.689 ;
     RECT  13.2 49.043 13.512 49.689 ;
     RECT  10.5 49.689 10.62 49.703 ;
     RECT  13.2 49.689 13.32 49.703 ;
     RECT  1.008 49.571 9.384 51.756 ;
     RECT  1.032 51.756 1.152 51.792 ;
     RECT  1.176 51.756 1.296 51.792 ;
     RECT  1.32 51.756 1.44 51.792 ;
     RECT  1.464 51.756 1.584 51.792 ;
     RECT  1.608 51.756 1.728 51.792 ;
     RECT  1.752 51.756 1.872 51.792 ;
     RECT  1.896 51.756 2.016 51.792 ;
     RECT  2.04 51.756 2.16 51.792 ;
     RECT  2.184 51.756 2.304 51.792 ;
     RECT  2.328 51.756 2.448 51.792 ;
     RECT  2.472 51.756 2.592 51.792 ;
     RECT  2.616 51.756 2.736 51.792 ;
     RECT  2.76 51.756 2.88 51.792 ;
     RECT  2.904 51.756 3.024 51.792 ;
     RECT  3.048 51.756 3.168 51.792 ;
     RECT  3.192 51.756 3.312 51.792 ;
     RECT  3.336 51.756 3.456 51.792 ;
     RECT  3.48 51.756 3.6 51.792 ;
     RECT  3.624 51.756 3.744 51.792 ;
     RECT  3.768 51.756 3.888 51.792 ;
     RECT  3.912 51.756 4.032 51.792 ;
     RECT  4.056 51.756 4.176 51.792 ;
     RECT  4.2 51.756 4.32 51.792 ;
     RECT  4.344 51.756 4.464 51.792 ;
     RECT  4.488 51.756 4.608 51.792 ;
     RECT  4.632 51.756 4.752 51.792 ;
     RECT  4.776 51.756 4.896 51.792 ;
     RECT  4.92 51.756 5.04 51.792 ;
     RECT  5.064 51.756 5.184 51.792 ;
     RECT  5.208 51.756 5.328 51.792 ;
     RECT  5.352 51.756 5.472 51.792 ;
     RECT  5.496 51.756 5.616 51.792 ;
     RECT  5.64 51.756 5.76 51.792 ;
     RECT  5.784 51.756 5.904 51.792 ;
     RECT  5.928 51.756 6.048 51.792 ;
     RECT  6.072 51.756 6.192 51.792 ;
     RECT  6.216 51.756 6.336 51.792 ;
     RECT  6.36 51.756 6.48 51.792 ;
     RECT  6.504 51.756 6.624 51.792 ;
     RECT  6.648 51.756 6.768 51.792 ;
     RECT  6.792 51.756 6.912 51.792 ;
     RECT  6.936 51.756 7.056 51.792 ;
     RECT  7.08 51.756 7.2 51.792 ;
     RECT  7.224 51.756 7.344 51.792 ;
     RECT  7.368 51.756 7.488 51.792 ;
     RECT  7.512 51.756 7.632 51.792 ;
     RECT  7.656 51.756 7.776 51.792 ;
     RECT  7.8 51.756 7.92 51.792 ;
     RECT  7.944 51.756 8.064 51.792 ;
     RECT  8.088 51.756 8.208 51.792 ;
     RECT  8.232 51.756 8.352 51.792 ;
     RECT  8.376 51.756 8.496 51.792 ;
     RECT  8.52 51.756 8.64 51.792 ;
     RECT  8.664 51.756 8.784 51.792 ;
     RECT  8.808 51.756 8.928 51.792 ;
     RECT  8.952 51.756 9.072 51.792 ;
     RECT  9.096 51.756 9.216 51.792 ;
     RECT  9.24 51.756 9.36 51.792 ;
     RECT  5.976 2.197 7.248 2.773 ;
     RECT  3.432 2.245 4.464 2.485 ;
     RECT  8.112 5.029 9.12 5.461 ;
     RECT  9.144 5.029 10.5 5.845 ;
     RECT  9.192 5.845 10.5 6.709 ;
     RECT  9.432 6.709 10.5 7.765 ;
     RECT  0.216 9.107 0.264 10.597 ;
     RECT  0.264 14.579 0.36 15.781 ;
     RECT  0.192 14.915 0.24 15.925 ;
     RECT  0.312 15.781 0.36 15.877 ;
     RECT  0.168 18.611 0.312 19.813 ;
     RECT  0.216 20.579 0.312 22.021 ;
     RECT  0.144 21.779 0.192 22.885 ;
     RECT  2.208 25.043 2.256 25.141 ;
     RECT  1.176 25.141 2.256 25.331 ;
     RECT  0.408 25.331 0.552 26.629 ;
     RECT  0.192 26.819 0.288 26.867 ;
     RECT  0.192 26.867 0.528 27.107 ;
     RECT  0.192 27.107 0.264 28.165 ;
     RECT  0.216 28.165 0.264 28.453 ;
     RECT  1.176 35.989 2.208 36.275 ;
     RECT  0.192 42.707 0.216 43.333 ;
     RECT  0.192 43.333 0.432 43.765 ;
     RECT  0.192 43.765 0.24 43.813 ;
     RECT  1.176 44.725 2.16 46.069 ;
     RECT  11.784 46.211 13.2 47.269 ;
     RECT  9.384 49.571 10.5 49.703 ;
  END
END ot_s81_cfg7_seq
END LIBRARY
